# Placeholder macro written by tools/chip_assembly/macros.py
# kind: tile; a die-assembly tile at 1/4 scale less the die channel; operand in and result out registered at its spine-facing edge (the physical tile's edge registers, ot_chip_v41x_ptile NP stages); routes M2-M7 inside (obstructed), die wiring passes over it on M8/M9
VERSION 5.7 ;
BUSBITCHARS "[]" ;
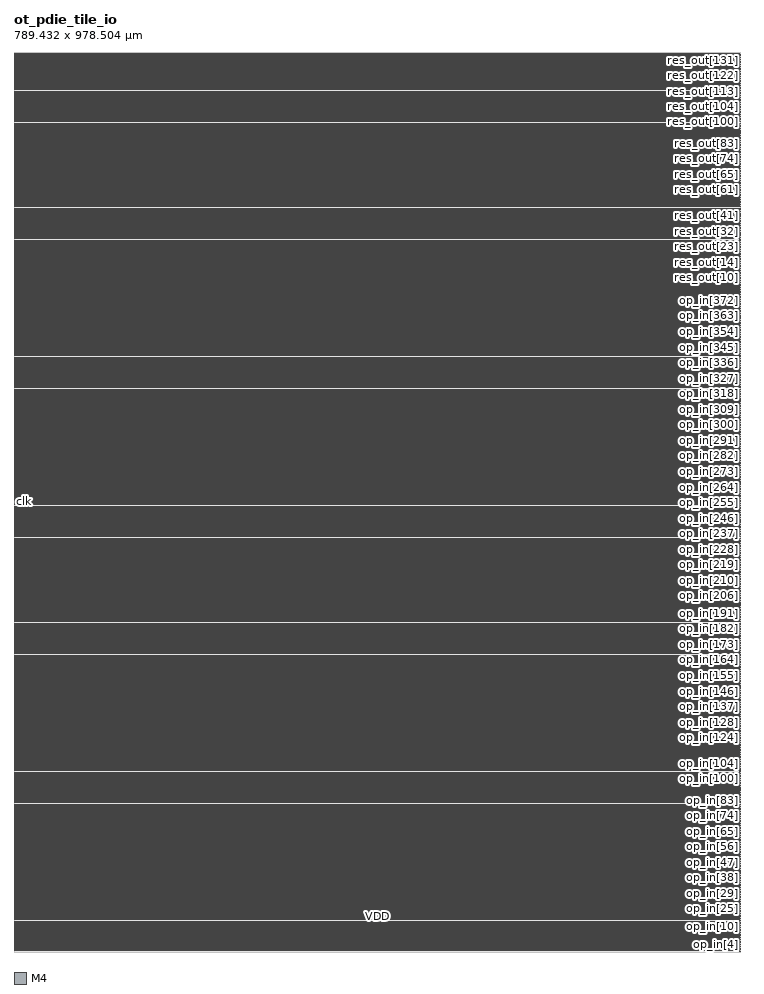
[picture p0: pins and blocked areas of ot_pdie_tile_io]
MACRO ot_pdie_tile_io
  FOREIGN ot_pdie_tile_io 0 0 ;
  SYMMETRY X Y ;
  SIZE 789.432 BY 978.504 ;
  CLASS BLOCK ;
  PIN clk
    DIRECTION INPUT ;
    USE SIGNAL ;
    SHAPE ABUTMENT ;
    PORT
      LAYER M4 ;
      RECT 0.000 489.264 0.192 489.288 ;
    END
  END clk
  PIN op_in[0]
    DIRECTION INPUT ;
    USE SIGNAL ;
    SHAPE ABUTMENT ;
    PORT
      LAYER M4 ;
      RECT 789.240 0.528 789.432 0.552 ;
    END
  END op_in[0]
  PIN op_in[1]
    DIRECTION INPUT ;
    USE SIGNAL ;
    SHAPE ABUTMENT ;
    PORT
      LAYER M4 ;
      RECT 789.240 2.400 789.432 2.424 ;
    END
  END op_in[1]
  PIN op_in[2]
    DIRECTION INPUT ;
    USE SIGNAL ;
    SHAPE ABUTMENT ;
    PORT
      LAYER M4 ;
      RECT 789.240 4.272 789.432 4.296 ;
    END
  END op_in[2]
  PIN op_in[3]
    DIRECTION INPUT ;
    USE SIGNAL ;
    SHAPE ABUTMENT ;
    PORT
      LAYER M4 ;
      RECT 789.240 6.144 789.432 6.168 ;
    END
  END op_in[3]
  PIN op_in[4]
    DIRECTION INPUT ;
    USE SIGNAL ;
    SHAPE ABUTMENT ;
    PORT
      LAYER M4 ;
      RECT 789.240 8.016 789.432 8.040 ;
    END
  END op_in[4]
  PIN op_in[5]
    DIRECTION INPUT ;
    USE SIGNAL ;
    SHAPE ABUTMENT ;
    PORT
      LAYER M4 ;
      RECT 789.240 9.888 789.432 9.912 ;
    END
  END op_in[5]
  PIN op_in[6]
    DIRECTION INPUT ;
    USE SIGNAL ;
    SHAPE ABUTMENT ;
    PORT
      LAYER M4 ;
      RECT 789.240 11.760 789.432 11.784 ;
    END
  END op_in[6]
  PIN op_in[7]
    DIRECTION INPUT ;
    USE SIGNAL ;
    SHAPE ABUTMENT ;
    PORT
      LAYER M4 ;
      RECT 789.240 13.680 789.432 13.704 ;
    END
  END op_in[7]
  PIN op_in[8]
    DIRECTION INPUT ;
    USE SIGNAL ;
    SHAPE ABUTMENT ;
    PORT
      LAYER M4 ;
      RECT 789.240 15.552 789.432 15.576 ;
    END
  END op_in[8]
  PIN op_in[9]
    DIRECTION INPUT ;
    USE SIGNAL ;
    SHAPE ABUTMENT ;
    PORT
      LAYER M4 ;
      RECT 789.240 17.424 789.432 17.448 ;
    END
  END op_in[9]
  PIN op_in[10]
    DIRECTION INPUT ;
    USE SIGNAL ;
    SHAPE ABUTMENT ;
    PORT
      LAYER M4 ;
      RECT 789.240 19.296 789.432 19.320 ;
    END
  END op_in[10]
  PIN op_in[11]
    DIRECTION INPUT ;
    USE SIGNAL ;
    SHAPE ABUTMENT ;
    PORT
      LAYER M4 ;
      RECT 789.240 21.168 789.432 21.192 ;
    END
  END op_in[11]
  PIN op_in[12]
    DIRECTION INPUT ;
    USE SIGNAL ;
    SHAPE ABUTMENT ;
    PORT
      LAYER M4 ;
      RECT 789.240 23.040 789.432 23.064 ;
    END
  END op_in[12]
  PIN op_in[13]
    DIRECTION INPUT ;
    USE SIGNAL ;
    SHAPE ABUTMENT ;
    PORT
      LAYER M4 ;
      RECT 789.240 24.960 789.432 24.984 ;
    END
  END op_in[13]
  PIN op_in[14]
    DIRECTION INPUT ;
    USE SIGNAL ;
    SHAPE ABUTMENT ;
    PORT
      LAYER M4 ;
      RECT 789.240 26.832 789.432 26.856 ;
    END
  END op_in[14]
  PIN op_in[15]
    DIRECTION INPUT ;
    USE SIGNAL ;
    SHAPE ABUTMENT ;
    PORT
      LAYER M4 ;
      RECT 789.240 28.704 789.432 28.728 ;
    END
  END op_in[15]
  PIN op_in[16]
    DIRECTION INPUT ;
    USE SIGNAL ;
    SHAPE ABUTMENT ;
    PORT
      LAYER M4 ;
      RECT 789.240 30.576 789.432 30.600 ;
    END
  END op_in[16]
  PIN op_in[17]
    DIRECTION INPUT ;
    USE SIGNAL ;
    SHAPE ABUTMENT ;
    PORT
      LAYER M4 ;
      RECT 789.240 32.448 789.432 32.472 ;
    END
  END op_in[17]
  PIN op_in[18]
    DIRECTION INPUT ;
    USE SIGNAL ;
    SHAPE ABUTMENT ;
    PORT
      LAYER M4 ;
      RECT 789.240 34.320 789.432 34.344 ;
    END
  END op_in[18]
  PIN op_in[19]
    DIRECTION INPUT ;
    USE SIGNAL ;
    SHAPE ABUTMENT ;
    PORT
      LAYER M4 ;
      RECT 789.240 36.240 789.432 36.264 ;
    END
  END op_in[19]
  PIN op_in[20]
    DIRECTION INPUT ;
    USE SIGNAL ;
    SHAPE ABUTMENT ;
    PORT
      LAYER M4 ;
      RECT 789.240 38.112 789.432 38.136 ;
    END
  END op_in[20]
  PIN op_in[21]
    DIRECTION INPUT ;
    USE SIGNAL ;
    SHAPE ABUTMENT ;
    PORT
      LAYER M4 ;
      RECT 789.240 39.984 789.432 40.008 ;
    END
  END op_in[21]
  PIN op_in[22]
    DIRECTION INPUT ;
    USE SIGNAL ;
    SHAPE ABUTMENT ;
    PORT
      LAYER M4 ;
      RECT 789.240 41.856 789.432 41.880 ;
    END
  END op_in[22]
  PIN op_in[23]
    DIRECTION INPUT ;
    USE SIGNAL ;
    SHAPE ABUTMENT ;
    PORT
      LAYER M4 ;
      RECT 789.240 43.728 789.432 43.752 ;
    END
  END op_in[23]
  PIN op_in[24]
    DIRECTION INPUT ;
    USE SIGNAL ;
    SHAPE ABUTMENT ;
    PORT
      LAYER M4 ;
      RECT 789.240 45.600 789.432 45.624 ;
    END
  END op_in[24]
  PIN op_in[25]
    DIRECTION INPUT ;
    USE SIGNAL ;
    SHAPE ABUTMENT ;
    PORT
      LAYER M4 ;
      RECT 789.240 47.520 789.432 47.544 ;
    END
  END op_in[25]
  PIN op_in[26]
    DIRECTION INPUT ;
    USE SIGNAL ;
    SHAPE ABUTMENT ;
    PORT
      LAYER M4 ;
      RECT 789.240 49.392 789.432 49.416 ;
    END
  END op_in[26]
  PIN op_in[27]
    DIRECTION INPUT ;
    USE SIGNAL ;
    SHAPE ABUTMENT ;
    PORT
      LAYER M4 ;
      RECT 789.240 51.264 789.432 51.288 ;
    END
  END op_in[27]
  PIN op_in[28]
    DIRECTION INPUT ;
    USE SIGNAL ;
    SHAPE ABUTMENT ;
    PORT
      LAYER M4 ;
      RECT 789.240 53.136 789.432 53.160 ;
    END
  END op_in[28]
  PIN op_in[29]
    DIRECTION INPUT ;
    USE SIGNAL ;
    SHAPE ABUTMENT ;
    PORT
      LAYER M4 ;
      RECT 789.240 55.008 789.432 55.032 ;
    END
  END op_in[29]
  PIN op_in[30]
    DIRECTION INPUT ;
    USE SIGNAL ;
    SHAPE ABUTMENT ;
    PORT
      LAYER M4 ;
      RECT 789.240 56.880 789.432 56.904 ;
    END
  END op_in[30]
  PIN op_in[31]
    DIRECTION INPUT ;
    USE SIGNAL ;
    SHAPE ABUTMENT ;
    PORT
      LAYER M4 ;
      RECT 789.240 58.800 789.432 58.824 ;
    END
  END op_in[31]
  PIN op_in[32]
    DIRECTION INPUT ;
    USE SIGNAL ;
    SHAPE ABUTMENT ;
    PORT
      LAYER M4 ;
      RECT 789.240 60.672 789.432 60.696 ;
    END
  END op_in[32]
  PIN op_in[33]
    DIRECTION INPUT ;
    USE SIGNAL ;
    SHAPE ABUTMENT ;
    PORT
      LAYER M4 ;
      RECT 789.240 62.544 789.432 62.568 ;
    END
  END op_in[33]
  PIN op_in[34]
    DIRECTION INPUT ;
    USE SIGNAL ;
    SHAPE ABUTMENT ;
    PORT
      LAYER M4 ;
      RECT 789.240 64.416 789.432 64.440 ;
    END
  END op_in[34]
  PIN op_in[35]
    DIRECTION INPUT ;
    USE SIGNAL ;
    SHAPE ABUTMENT ;
    PORT
      LAYER M4 ;
      RECT 789.240 66.288 789.432 66.312 ;
    END
  END op_in[35]
  PIN op_in[36]
    DIRECTION INPUT ;
    USE SIGNAL ;
    SHAPE ABUTMENT ;
    PORT
      LAYER M4 ;
      RECT 789.240 68.160 789.432 68.184 ;
    END
  END op_in[36]
  PIN op_in[37]
    DIRECTION INPUT ;
    USE SIGNAL ;
    SHAPE ABUTMENT ;
    PORT
      LAYER M4 ;
      RECT 789.240 70.032 789.432 70.056 ;
    END
  END op_in[37]
  PIN op_in[38]
    DIRECTION INPUT ;
    USE SIGNAL ;
    SHAPE ABUTMENT ;
    PORT
      LAYER M4 ;
      RECT 789.240 71.952 789.432 71.976 ;
    END
  END op_in[38]
  PIN op_in[39]
    DIRECTION INPUT ;
    USE SIGNAL ;
    SHAPE ABUTMENT ;
    PORT
      LAYER M4 ;
      RECT 789.240 73.824 789.432 73.848 ;
    END
  END op_in[39]
  PIN op_in[40]
    DIRECTION INPUT ;
    USE SIGNAL ;
    SHAPE ABUTMENT ;
    PORT
      LAYER M4 ;
      RECT 789.240 75.696 789.432 75.720 ;
    END
  END op_in[40]
  PIN op_in[41]
    DIRECTION INPUT ;
    USE SIGNAL ;
    SHAPE ABUTMENT ;
    PORT
      LAYER M4 ;
      RECT 789.240 77.568 789.432 77.592 ;
    END
  END op_in[41]
  PIN op_in[42]
    DIRECTION INPUT ;
    USE SIGNAL ;
    SHAPE ABUTMENT ;
    PORT
      LAYER M4 ;
      RECT 789.240 79.440 789.432 79.464 ;
    END
  END op_in[42]
  PIN op_in[43]
    DIRECTION INPUT ;
    USE SIGNAL ;
    SHAPE ABUTMENT ;
    PORT
      LAYER M4 ;
      RECT 789.240 81.312 789.432 81.336 ;
    END
  END op_in[43]
  PIN op_in[44]
    DIRECTION INPUT ;
    USE SIGNAL ;
    SHAPE ABUTMENT ;
    PORT
      LAYER M4 ;
      RECT 789.240 83.232 789.432 83.256 ;
    END
  END op_in[44]
  PIN op_in[45]
    DIRECTION INPUT ;
    USE SIGNAL ;
    SHAPE ABUTMENT ;
    PORT
      LAYER M4 ;
      RECT 789.240 85.104 789.432 85.128 ;
    END
  END op_in[45]
  PIN op_in[46]
    DIRECTION INPUT ;
    USE SIGNAL ;
    SHAPE ABUTMENT ;
    PORT
      LAYER M4 ;
      RECT 789.240 86.976 789.432 87.000 ;
    END
  END op_in[46]
  PIN op_in[47]
    DIRECTION INPUT ;
    USE SIGNAL ;
    SHAPE ABUTMENT ;
    PORT
      LAYER M4 ;
      RECT 789.240 88.848 789.432 88.872 ;
    END
  END op_in[47]
  PIN op_in[48]
    DIRECTION INPUT ;
    USE SIGNAL ;
    SHAPE ABUTMENT ;
    PORT
      LAYER M4 ;
      RECT 789.240 90.720 789.432 90.744 ;
    END
  END op_in[48]
  PIN op_in[49]
    DIRECTION INPUT ;
    USE SIGNAL ;
    SHAPE ABUTMENT ;
    PORT
      LAYER M4 ;
      RECT 789.240 92.592 789.432 92.616 ;
    END
  END op_in[49]
  PIN op_in[50]
    DIRECTION INPUT ;
    USE SIGNAL ;
    SHAPE ABUTMENT ;
    PORT
      LAYER M4 ;
      RECT 789.240 94.512 789.432 94.536 ;
    END
  END op_in[50]
  PIN op_in[51]
    DIRECTION INPUT ;
    USE SIGNAL ;
    SHAPE ABUTMENT ;
    PORT
      LAYER M4 ;
      RECT 789.240 96.384 789.432 96.408 ;
    END
  END op_in[51]
  PIN op_in[52]
    DIRECTION INPUT ;
    USE SIGNAL ;
    SHAPE ABUTMENT ;
    PORT
      LAYER M4 ;
      RECT 789.240 98.256 789.432 98.280 ;
    END
  END op_in[52]
  PIN op_in[53]
    DIRECTION INPUT ;
    USE SIGNAL ;
    SHAPE ABUTMENT ;
    PORT
      LAYER M4 ;
      RECT 789.240 100.128 789.432 100.152 ;
    END
  END op_in[53]
  PIN op_in[54]
    DIRECTION INPUT ;
    USE SIGNAL ;
    SHAPE ABUTMENT ;
    PORT
      LAYER M4 ;
      RECT 789.240 102.000 789.432 102.024 ;
    END
  END op_in[54]
  PIN op_in[55]
    DIRECTION INPUT ;
    USE SIGNAL ;
    SHAPE ABUTMENT ;
    PORT
      LAYER M4 ;
      RECT 789.240 103.872 789.432 103.896 ;
    END
  END op_in[55]
  PIN op_in[56]
    DIRECTION INPUT ;
    USE SIGNAL ;
    SHAPE ABUTMENT ;
    PORT
      LAYER M4 ;
      RECT 789.240 105.792 789.432 105.816 ;
    END
  END op_in[56]
  PIN op_in[57]
    DIRECTION INPUT ;
    USE SIGNAL ;
    SHAPE ABUTMENT ;
    PORT
      LAYER M4 ;
      RECT 789.240 107.664 789.432 107.688 ;
    END
  END op_in[57]
  PIN op_in[58]
    DIRECTION INPUT ;
    USE SIGNAL ;
    SHAPE ABUTMENT ;
    PORT
      LAYER M4 ;
      RECT 789.240 109.536 789.432 109.560 ;
    END
  END op_in[58]
  PIN op_in[59]
    DIRECTION INPUT ;
    USE SIGNAL ;
    SHAPE ABUTMENT ;
    PORT
      LAYER M4 ;
      RECT 789.240 111.408 789.432 111.432 ;
    END
  END op_in[59]
  PIN op_in[60]
    DIRECTION INPUT ;
    USE SIGNAL ;
    SHAPE ABUTMENT ;
    PORT
      LAYER M4 ;
      RECT 789.240 113.280 789.432 113.304 ;
    END
  END op_in[60]
  PIN op_in[61]
    DIRECTION INPUT ;
    USE SIGNAL ;
    SHAPE ABUTMENT ;
    PORT
      LAYER M4 ;
      RECT 789.240 115.152 789.432 115.176 ;
    END
  END op_in[61]
  PIN op_in[62]
    DIRECTION INPUT ;
    USE SIGNAL ;
    SHAPE ABUTMENT ;
    PORT
      LAYER M4 ;
      RECT 789.240 117.072 789.432 117.096 ;
    END
  END op_in[62]
  PIN op_in[63]
    DIRECTION INPUT ;
    USE SIGNAL ;
    SHAPE ABUTMENT ;
    PORT
      LAYER M4 ;
      RECT 789.240 118.944 789.432 118.968 ;
    END
  END op_in[63]
  PIN op_in[64]
    DIRECTION INPUT ;
    USE SIGNAL ;
    SHAPE ABUTMENT ;
    PORT
      LAYER M4 ;
      RECT 789.240 120.816 789.432 120.840 ;
    END
  END op_in[64]
  PIN op_in[65]
    DIRECTION INPUT ;
    USE SIGNAL ;
    SHAPE ABUTMENT ;
    PORT
      LAYER M4 ;
      RECT 789.240 122.688 789.432 122.712 ;
    END
  END op_in[65]
  PIN op_in[66]
    DIRECTION INPUT ;
    USE SIGNAL ;
    SHAPE ABUTMENT ;
    PORT
      LAYER M4 ;
      RECT 789.240 124.560 789.432 124.584 ;
    END
  END op_in[66]
  PIN op_in[67]
    DIRECTION INPUT ;
    USE SIGNAL ;
    SHAPE ABUTMENT ;
    PORT
      LAYER M4 ;
      RECT 789.240 126.432 789.432 126.456 ;
    END
  END op_in[67]
  PIN op_in[68]
    DIRECTION INPUT ;
    USE SIGNAL ;
    SHAPE ABUTMENT ;
    PORT
      LAYER M4 ;
      RECT 789.240 128.304 789.432 128.328 ;
    END
  END op_in[68]
  PIN op_in[69]
    DIRECTION INPUT ;
    USE SIGNAL ;
    SHAPE ABUTMENT ;
    PORT
      LAYER M4 ;
      RECT 789.240 130.224 789.432 130.248 ;
    END
  END op_in[69]
  PIN op_in[70]
    DIRECTION INPUT ;
    USE SIGNAL ;
    SHAPE ABUTMENT ;
    PORT
      LAYER M4 ;
      RECT 789.240 132.096 789.432 132.120 ;
    END
  END op_in[70]
  PIN op_in[71]
    DIRECTION INPUT ;
    USE SIGNAL ;
    SHAPE ABUTMENT ;
    PORT
      LAYER M4 ;
      RECT 789.240 133.968 789.432 133.992 ;
    END
  END op_in[71]
  PIN op_in[72]
    DIRECTION INPUT ;
    USE SIGNAL ;
    SHAPE ABUTMENT ;
    PORT
      LAYER M4 ;
      RECT 789.240 135.840 789.432 135.864 ;
    END
  END op_in[72]
  PIN op_in[73]
    DIRECTION INPUT ;
    USE SIGNAL ;
    SHAPE ABUTMENT ;
    PORT
      LAYER M4 ;
      RECT 789.240 137.712 789.432 137.736 ;
    END
  END op_in[73]
  PIN op_in[74]
    DIRECTION INPUT ;
    USE SIGNAL ;
    SHAPE ABUTMENT ;
    PORT
      LAYER M4 ;
      RECT 789.240 139.584 789.432 139.608 ;
    END
  END op_in[74]
  PIN op_in[75]
    DIRECTION INPUT ;
    USE SIGNAL ;
    SHAPE ABUTMENT ;
    PORT
      LAYER M4 ;
      RECT 789.240 141.504 789.432 141.528 ;
    END
  END op_in[75]
  PIN op_in[76]
    DIRECTION INPUT ;
    USE SIGNAL ;
    SHAPE ABUTMENT ;
    PORT
      LAYER M4 ;
      RECT 789.240 143.376 789.432 143.400 ;
    END
  END op_in[76]
  PIN op_in[77]
    DIRECTION INPUT ;
    USE SIGNAL ;
    SHAPE ABUTMENT ;
    PORT
      LAYER M4 ;
      RECT 789.240 145.248 789.432 145.272 ;
    END
  END op_in[77]
  PIN op_in[78]
    DIRECTION INPUT ;
    USE SIGNAL ;
    SHAPE ABUTMENT ;
    PORT
      LAYER M4 ;
      RECT 789.240 147.120 789.432 147.144 ;
    END
  END op_in[78]
  PIN op_in[79]
    DIRECTION INPUT ;
    USE SIGNAL ;
    SHAPE ABUTMENT ;
    PORT
      LAYER M4 ;
      RECT 789.240 148.992 789.432 149.016 ;
    END
  END op_in[79]
  PIN op_in[80]
    DIRECTION INPUT ;
    USE SIGNAL ;
    SHAPE ABUTMENT ;
    PORT
      LAYER M4 ;
      RECT 789.240 150.864 789.432 150.888 ;
    END
  END op_in[80]
  PIN op_in[81]
    DIRECTION INPUT ;
    USE SIGNAL ;
    SHAPE ABUTMENT ;
    PORT
      LAYER M4 ;
      RECT 789.240 152.784 789.432 152.808 ;
    END
  END op_in[81]
  PIN op_in[82]
    DIRECTION INPUT ;
    USE SIGNAL ;
    SHAPE ABUTMENT ;
    PORT
      LAYER M4 ;
      RECT 789.240 154.656 789.432 154.680 ;
    END
  END op_in[82]
  PIN op_in[83]
    DIRECTION INPUT ;
    USE SIGNAL ;
    SHAPE ABUTMENT ;
    PORT
      LAYER M4 ;
      RECT 789.240 156.528 789.432 156.552 ;
    END
  END op_in[83]
  PIN op_in[84]
    DIRECTION INPUT ;
    USE SIGNAL ;
    SHAPE ABUTMENT ;
    PORT
      LAYER M4 ;
      RECT 789.240 158.400 789.432 158.424 ;
    END
  END op_in[84]
  PIN op_in[85]
    DIRECTION INPUT ;
    USE SIGNAL ;
    SHAPE ABUTMENT ;
    PORT
      LAYER M4 ;
      RECT 789.240 160.272 789.432 160.296 ;
    END
  END op_in[85]
  PIN op_in[86]
    DIRECTION INPUT ;
    USE SIGNAL ;
    SHAPE ABUTMENT ;
    PORT
      LAYER M4 ;
      RECT 789.240 162.144 789.432 162.168 ;
    END
  END op_in[86]
  PIN op_in[87]
    DIRECTION INPUT ;
    USE SIGNAL ;
    SHAPE ABUTMENT ;
    PORT
      LAYER M4 ;
      RECT 789.240 164.064 789.432 164.088 ;
    END
  END op_in[87]
  PIN op_in[88]
    DIRECTION INPUT ;
    USE SIGNAL ;
    SHAPE ABUTMENT ;
    PORT
      LAYER M4 ;
      RECT 789.240 165.936 789.432 165.960 ;
    END
  END op_in[88]
  PIN op_in[89]
    DIRECTION INPUT ;
    USE SIGNAL ;
    SHAPE ABUTMENT ;
    PORT
      LAYER M4 ;
      RECT 789.240 167.808 789.432 167.832 ;
    END
  END op_in[89]
  PIN op_in[90]
    DIRECTION INPUT ;
    USE SIGNAL ;
    SHAPE ABUTMENT ;
    PORT
      LAYER M4 ;
      RECT 789.240 169.680 789.432 169.704 ;
    END
  END op_in[90]
  PIN op_in[91]
    DIRECTION INPUT ;
    USE SIGNAL ;
    SHAPE ABUTMENT ;
    PORT
      LAYER M4 ;
      RECT 789.240 171.552 789.432 171.576 ;
    END
  END op_in[91]
  PIN op_in[92]
    DIRECTION INPUT ;
    USE SIGNAL ;
    SHAPE ABUTMENT ;
    PORT
      LAYER M4 ;
      RECT 789.240 173.424 789.432 173.448 ;
    END
  END op_in[92]
  PIN op_in[93]
    DIRECTION INPUT ;
    USE SIGNAL ;
    SHAPE ABUTMENT ;
    PORT
      LAYER M4 ;
      RECT 789.240 175.344 789.432 175.368 ;
    END
  END op_in[93]
  PIN op_in[94]
    DIRECTION INPUT ;
    USE SIGNAL ;
    SHAPE ABUTMENT ;
    PORT
      LAYER M4 ;
      RECT 789.240 177.216 789.432 177.240 ;
    END
  END op_in[94]
  PIN op_in[95]
    DIRECTION INPUT ;
    USE SIGNAL ;
    SHAPE ABUTMENT ;
    PORT
      LAYER M4 ;
      RECT 789.240 179.088 789.432 179.112 ;
    END
  END op_in[95]
  PIN op_in[96]
    DIRECTION INPUT ;
    USE SIGNAL ;
    SHAPE ABUTMENT ;
    PORT
      LAYER M4 ;
      RECT 789.240 180.960 789.432 180.984 ;
    END
  END op_in[96]
  PIN op_in[97]
    DIRECTION INPUT ;
    USE SIGNAL ;
    SHAPE ABUTMENT ;
    PORT
      LAYER M4 ;
      RECT 789.240 182.832 789.432 182.856 ;
    END
  END op_in[97]
  PIN op_in[98]
    DIRECTION INPUT ;
    USE SIGNAL ;
    SHAPE ABUTMENT ;
    PORT
      LAYER M4 ;
      RECT 789.240 184.704 789.432 184.728 ;
    END
  END op_in[98]
  PIN op_in[99]
    DIRECTION INPUT ;
    USE SIGNAL ;
    SHAPE ABUTMENT ;
    PORT
      LAYER M4 ;
      RECT 789.240 186.576 789.432 186.600 ;
    END
  END op_in[99]
  PIN op_in[100]
    DIRECTION INPUT ;
    USE SIGNAL ;
    SHAPE ABUTMENT ;
    PORT
      LAYER M4 ;
      RECT 789.240 188.496 789.432 188.520 ;
    END
  END op_in[100]
  PIN op_in[101]
    DIRECTION INPUT ;
    USE SIGNAL ;
    SHAPE ABUTMENT ;
    PORT
      LAYER M4 ;
      RECT 789.240 190.368 789.432 190.392 ;
    END
  END op_in[101]
  PIN op_in[102]
    DIRECTION INPUT ;
    USE SIGNAL ;
    SHAPE ABUTMENT ;
    PORT
      LAYER M4 ;
      RECT 789.240 192.240 789.432 192.264 ;
    END
  END op_in[102]
  PIN op_in[103]
    DIRECTION INPUT ;
    USE SIGNAL ;
    SHAPE ABUTMENT ;
    PORT
      LAYER M4 ;
      RECT 789.240 194.112 789.432 194.136 ;
    END
  END op_in[103]
  PIN op_in[104]
    DIRECTION INPUT ;
    USE SIGNAL ;
    SHAPE ABUTMENT ;
    PORT
      LAYER M4 ;
      RECT 789.240 195.984 789.432 196.008 ;
    END
  END op_in[104]
  PIN op_in[105]
    DIRECTION INPUT ;
    USE SIGNAL ;
    SHAPE ABUTMENT ;
    PORT
      LAYER M4 ;
      RECT 789.240 197.856 789.432 197.880 ;
    END
  END op_in[105]
  PIN op_in[106]
    DIRECTION INPUT ;
    USE SIGNAL ;
    SHAPE ABUTMENT ;
    PORT
      LAYER M4 ;
      RECT 789.240 199.776 789.432 199.800 ;
    END
  END op_in[106]
  PIN op_in[107]
    DIRECTION INPUT ;
    USE SIGNAL ;
    SHAPE ABUTMENT ;
    PORT
      LAYER M4 ;
      RECT 789.240 201.648 789.432 201.672 ;
    END
  END op_in[107]
  PIN op_in[108]
    DIRECTION INPUT ;
    USE SIGNAL ;
    SHAPE ABUTMENT ;
    PORT
      LAYER M4 ;
      RECT 789.240 203.520 789.432 203.544 ;
    END
  END op_in[108]
  PIN op_in[109]
    DIRECTION INPUT ;
    USE SIGNAL ;
    SHAPE ABUTMENT ;
    PORT
      LAYER M4 ;
      RECT 789.240 205.392 789.432 205.416 ;
    END
  END op_in[109]
  PIN op_in[110]
    DIRECTION INPUT ;
    USE SIGNAL ;
    SHAPE ABUTMENT ;
    PORT
      LAYER M4 ;
      RECT 789.240 207.264 789.432 207.288 ;
    END
  END op_in[110]
  PIN op_in[111]
    DIRECTION INPUT ;
    USE SIGNAL ;
    SHAPE ABUTMENT ;
    PORT
      LAYER M4 ;
      RECT 789.240 209.136 789.432 209.160 ;
    END
  END op_in[111]
  PIN op_in[112]
    DIRECTION INPUT ;
    USE SIGNAL ;
    SHAPE ABUTMENT ;
    PORT
      LAYER M4 ;
      RECT 789.240 211.056 789.432 211.080 ;
    END
  END op_in[112]
  PIN op_in[113]
    DIRECTION INPUT ;
    USE SIGNAL ;
    SHAPE ABUTMENT ;
    PORT
      LAYER M4 ;
      RECT 789.240 212.928 789.432 212.952 ;
    END
  END op_in[113]
  PIN op_in[114]
    DIRECTION INPUT ;
    USE SIGNAL ;
    SHAPE ABUTMENT ;
    PORT
      LAYER M4 ;
      RECT 789.240 214.800 789.432 214.824 ;
    END
  END op_in[114]
  PIN op_in[115]
    DIRECTION INPUT ;
    USE SIGNAL ;
    SHAPE ABUTMENT ;
    PORT
      LAYER M4 ;
      RECT 789.240 216.672 789.432 216.696 ;
    END
  END op_in[115]
  PIN op_in[116]
    DIRECTION INPUT ;
    USE SIGNAL ;
    SHAPE ABUTMENT ;
    PORT
      LAYER M4 ;
      RECT 789.240 218.544 789.432 218.568 ;
    END
  END op_in[116]
  PIN op_in[117]
    DIRECTION INPUT ;
    USE SIGNAL ;
    SHAPE ABUTMENT ;
    PORT
      LAYER M4 ;
      RECT 789.240 220.416 789.432 220.440 ;
    END
  END op_in[117]
  PIN op_in[118]
    DIRECTION INPUT ;
    USE SIGNAL ;
    SHAPE ABUTMENT ;
    PORT
      LAYER M4 ;
      RECT 789.240 222.336 789.432 222.360 ;
    END
  END op_in[118]
  PIN op_in[119]
    DIRECTION INPUT ;
    USE SIGNAL ;
    SHAPE ABUTMENT ;
    PORT
      LAYER M4 ;
      RECT 789.240 224.208 789.432 224.232 ;
    END
  END op_in[119]
  PIN op_in[120]
    DIRECTION INPUT ;
    USE SIGNAL ;
    SHAPE ABUTMENT ;
    PORT
      LAYER M4 ;
      RECT 789.240 226.080 789.432 226.104 ;
    END
  END op_in[120]
  PIN op_in[121]
    DIRECTION INPUT ;
    USE SIGNAL ;
    SHAPE ABUTMENT ;
    PORT
      LAYER M4 ;
      RECT 789.240 227.952 789.432 227.976 ;
    END
  END op_in[121]
  PIN op_in[122]
    DIRECTION INPUT ;
    USE SIGNAL ;
    SHAPE ABUTMENT ;
    PORT
      LAYER M4 ;
      RECT 789.240 229.824 789.432 229.848 ;
    END
  END op_in[122]
  PIN op_in[123]
    DIRECTION INPUT ;
    USE SIGNAL ;
    SHAPE ABUTMENT ;
    PORT
      LAYER M4 ;
      RECT 789.240 231.696 789.432 231.720 ;
    END
  END op_in[123]
  PIN op_in[124]
    DIRECTION INPUT ;
    USE SIGNAL ;
    SHAPE ABUTMENT ;
    PORT
      LAYER M4 ;
      RECT 789.240 233.616 789.432 233.640 ;
    END
  END op_in[124]
  PIN op_in[125]
    DIRECTION INPUT ;
    USE SIGNAL ;
    SHAPE ABUTMENT ;
    PORT
      LAYER M4 ;
      RECT 789.240 235.488 789.432 235.512 ;
    END
  END op_in[125]
  PIN op_in[126]
    DIRECTION INPUT ;
    USE SIGNAL ;
    SHAPE ABUTMENT ;
    PORT
      LAYER M4 ;
      RECT 789.240 237.360 789.432 237.384 ;
    END
  END op_in[126]
  PIN op_in[127]
    DIRECTION INPUT ;
    USE SIGNAL ;
    SHAPE ABUTMENT ;
    PORT
      LAYER M4 ;
      RECT 789.240 239.232 789.432 239.256 ;
    END
  END op_in[127]
  PIN op_in[128]
    DIRECTION INPUT ;
    USE SIGNAL ;
    SHAPE ABUTMENT ;
    PORT
      LAYER M4 ;
      RECT 789.240 241.104 789.432 241.128 ;
    END
  END op_in[128]
  PIN op_in[129]
    DIRECTION INPUT ;
    USE SIGNAL ;
    SHAPE ABUTMENT ;
    PORT
      LAYER M4 ;
      RECT 789.240 242.976 789.432 243.000 ;
    END
  END op_in[129]
  PIN op_in[130]
    DIRECTION INPUT ;
    USE SIGNAL ;
    SHAPE ABUTMENT ;
    PORT
      LAYER M4 ;
      RECT 789.240 244.896 789.432 244.920 ;
    END
  END op_in[130]
  PIN op_in[131]
    DIRECTION INPUT ;
    USE SIGNAL ;
    SHAPE ABUTMENT ;
    PORT
      LAYER M4 ;
      RECT 789.240 246.768 789.432 246.792 ;
    END
  END op_in[131]
  PIN op_in[132]
    DIRECTION INPUT ;
    USE SIGNAL ;
    SHAPE ABUTMENT ;
    PORT
      LAYER M4 ;
      RECT 789.240 248.640 789.432 248.664 ;
    END
  END op_in[132]
  PIN op_in[133]
    DIRECTION INPUT ;
    USE SIGNAL ;
    SHAPE ABUTMENT ;
    PORT
      LAYER M4 ;
      RECT 789.240 250.512 789.432 250.536 ;
    END
  END op_in[133]
  PIN op_in[134]
    DIRECTION INPUT ;
    USE SIGNAL ;
    SHAPE ABUTMENT ;
    PORT
      LAYER M4 ;
      RECT 789.240 252.384 789.432 252.408 ;
    END
  END op_in[134]
  PIN op_in[135]
    DIRECTION INPUT ;
    USE SIGNAL ;
    SHAPE ABUTMENT ;
    PORT
      LAYER M4 ;
      RECT 789.240 254.256 789.432 254.280 ;
    END
  END op_in[135]
  PIN op_in[136]
    DIRECTION INPUT ;
    USE SIGNAL ;
    SHAPE ABUTMENT ;
    PORT
      LAYER M4 ;
      RECT 789.240 256.128 789.432 256.152 ;
    END
  END op_in[136]
  PIN op_in[137]
    DIRECTION INPUT ;
    USE SIGNAL ;
    SHAPE ABUTMENT ;
    PORT
      LAYER M4 ;
      RECT 789.240 258.048 789.432 258.072 ;
    END
  END op_in[137]
  PIN op_in[138]
    DIRECTION INPUT ;
    USE SIGNAL ;
    SHAPE ABUTMENT ;
    PORT
      LAYER M4 ;
      RECT 789.240 259.920 789.432 259.944 ;
    END
  END op_in[138]
  PIN op_in[139]
    DIRECTION INPUT ;
    USE SIGNAL ;
    SHAPE ABUTMENT ;
    PORT
      LAYER M4 ;
      RECT 789.240 261.792 789.432 261.816 ;
    END
  END op_in[139]
  PIN op_in[140]
    DIRECTION INPUT ;
    USE SIGNAL ;
    SHAPE ABUTMENT ;
    PORT
      LAYER M4 ;
      RECT 789.240 263.664 789.432 263.688 ;
    END
  END op_in[140]
  PIN op_in[141]
    DIRECTION INPUT ;
    USE SIGNAL ;
    SHAPE ABUTMENT ;
    PORT
      LAYER M4 ;
      RECT 789.240 265.536 789.432 265.560 ;
    END
  END op_in[141]
  PIN op_in[142]
    DIRECTION INPUT ;
    USE SIGNAL ;
    SHAPE ABUTMENT ;
    PORT
      LAYER M4 ;
      RECT 789.240 267.408 789.432 267.432 ;
    END
  END op_in[142]
  PIN op_in[143]
    DIRECTION INPUT ;
    USE SIGNAL ;
    SHAPE ABUTMENT ;
    PORT
      LAYER M4 ;
      RECT 789.240 269.328 789.432 269.352 ;
    END
  END op_in[143]
  PIN op_in[144]
    DIRECTION INPUT ;
    USE SIGNAL ;
    SHAPE ABUTMENT ;
    PORT
      LAYER M4 ;
      RECT 789.240 271.200 789.432 271.224 ;
    END
  END op_in[144]
  PIN op_in[145]
    DIRECTION INPUT ;
    USE SIGNAL ;
    SHAPE ABUTMENT ;
    PORT
      LAYER M4 ;
      RECT 789.240 273.072 789.432 273.096 ;
    END
  END op_in[145]
  PIN op_in[146]
    DIRECTION INPUT ;
    USE SIGNAL ;
    SHAPE ABUTMENT ;
    PORT
      LAYER M4 ;
      RECT 789.240 274.944 789.432 274.968 ;
    END
  END op_in[146]
  PIN op_in[147]
    DIRECTION INPUT ;
    USE SIGNAL ;
    SHAPE ABUTMENT ;
    PORT
      LAYER M4 ;
      RECT 789.240 276.816 789.432 276.840 ;
    END
  END op_in[147]
  PIN op_in[148]
    DIRECTION INPUT ;
    USE SIGNAL ;
    SHAPE ABUTMENT ;
    PORT
      LAYER M4 ;
      RECT 789.240 278.688 789.432 278.712 ;
    END
  END op_in[148]
  PIN op_in[149]
    DIRECTION INPUT ;
    USE SIGNAL ;
    SHAPE ABUTMENT ;
    PORT
      LAYER M4 ;
      RECT 789.240 280.608 789.432 280.632 ;
    END
  END op_in[149]
  PIN op_in[150]
    DIRECTION INPUT ;
    USE SIGNAL ;
    SHAPE ABUTMENT ;
    PORT
      LAYER M4 ;
      RECT 789.240 282.480 789.432 282.504 ;
    END
  END op_in[150]
  PIN op_in[151]
    DIRECTION INPUT ;
    USE SIGNAL ;
    SHAPE ABUTMENT ;
    PORT
      LAYER M4 ;
      RECT 789.240 284.352 789.432 284.376 ;
    END
  END op_in[151]
  PIN op_in[152]
    DIRECTION INPUT ;
    USE SIGNAL ;
    SHAPE ABUTMENT ;
    PORT
      LAYER M4 ;
      RECT 789.240 286.224 789.432 286.248 ;
    END
  END op_in[152]
  PIN op_in[153]
    DIRECTION INPUT ;
    USE SIGNAL ;
    SHAPE ABUTMENT ;
    PORT
      LAYER M4 ;
      RECT 789.240 288.096 789.432 288.120 ;
    END
  END op_in[153]
  PIN op_in[154]
    DIRECTION INPUT ;
    USE SIGNAL ;
    SHAPE ABUTMENT ;
    PORT
      LAYER M4 ;
      RECT 789.240 289.968 789.432 289.992 ;
    END
  END op_in[154]
  PIN op_in[155]
    DIRECTION INPUT ;
    USE SIGNAL ;
    SHAPE ABUTMENT ;
    PORT
      LAYER M4 ;
      RECT 789.240 291.888 789.432 291.912 ;
    END
  END op_in[155]
  PIN op_in[156]
    DIRECTION INPUT ;
    USE SIGNAL ;
    SHAPE ABUTMENT ;
    PORT
      LAYER M4 ;
      RECT 789.240 293.760 789.432 293.784 ;
    END
  END op_in[156]
  PIN op_in[157]
    DIRECTION INPUT ;
    USE SIGNAL ;
    SHAPE ABUTMENT ;
    PORT
      LAYER M4 ;
      RECT 789.240 295.632 789.432 295.656 ;
    END
  END op_in[157]
  PIN op_in[158]
    DIRECTION INPUT ;
    USE SIGNAL ;
    SHAPE ABUTMENT ;
    PORT
      LAYER M4 ;
      RECT 789.240 297.504 789.432 297.528 ;
    END
  END op_in[158]
  PIN op_in[159]
    DIRECTION INPUT ;
    USE SIGNAL ;
    SHAPE ABUTMENT ;
    PORT
      LAYER M4 ;
      RECT 789.240 299.376 789.432 299.400 ;
    END
  END op_in[159]
  PIN op_in[160]
    DIRECTION INPUT ;
    USE SIGNAL ;
    SHAPE ABUTMENT ;
    PORT
      LAYER M4 ;
      RECT 789.240 301.248 789.432 301.272 ;
    END
  END op_in[160]
  PIN op_in[161]
    DIRECTION INPUT ;
    USE SIGNAL ;
    SHAPE ABUTMENT ;
    PORT
      LAYER M4 ;
      RECT 789.240 303.168 789.432 303.192 ;
    END
  END op_in[161]
  PIN op_in[162]
    DIRECTION INPUT ;
    USE SIGNAL ;
    SHAPE ABUTMENT ;
    PORT
      LAYER M4 ;
      RECT 789.240 305.040 789.432 305.064 ;
    END
  END op_in[162]
  PIN op_in[163]
    DIRECTION INPUT ;
    USE SIGNAL ;
    SHAPE ABUTMENT ;
    PORT
      LAYER M4 ;
      RECT 789.240 306.912 789.432 306.936 ;
    END
  END op_in[163]
  PIN op_in[164]
    DIRECTION INPUT ;
    USE SIGNAL ;
    SHAPE ABUTMENT ;
    PORT
      LAYER M4 ;
      RECT 789.240 308.784 789.432 308.808 ;
    END
  END op_in[164]
  PIN op_in[165]
    DIRECTION INPUT ;
    USE SIGNAL ;
    SHAPE ABUTMENT ;
    PORT
      LAYER M4 ;
      RECT 789.240 310.656 789.432 310.680 ;
    END
  END op_in[165]
  PIN op_in[166]
    DIRECTION INPUT ;
    USE SIGNAL ;
    SHAPE ABUTMENT ;
    PORT
      LAYER M4 ;
      RECT 789.240 312.528 789.432 312.552 ;
    END
  END op_in[166]
  PIN op_in[167]
    DIRECTION INPUT ;
    USE SIGNAL ;
    SHAPE ABUTMENT ;
    PORT
      LAYER M4 ;
      RECT 789.240 314.400 789.432 314.424 ;
    END
  END op_in[167]
  PIN op_in[168]
    DIRECTION INPUT ;
    USE SIGNAL ;
    SHAPE ABUTMENT ;
    PORT
      LAYER M4 ;
      RECT 789.240 316.320 789.432 316.344 ;
    END
  END op_in[168]
  PIN op_in[169]
    DIRECTION INPUT ;
    USE SIGNAL ;
    SHAPE ABUTMENT ;
    PORT
      LAYER M4 ;
      RECT 789.240 318.192 789.432 318.216 ;
    END
  END op_in[169]
  PIN op_in[170]
    DIRECTION INPUT ;
    USE SIGNAL ;
    SHAPE ABUTMENT ;
    PORT
      LAYER M4 ;
      RECT 789.240 320.064 789.432 320.088 ;
    END
  END op_in[170]
  PIN op_in[171]
    DIRECTION INPUT ;
    USE SIGNAL ;
    SHAPE ABUTMENT ;
    PORT
      LAYER M4 ;
      RECT 789.240 321.936 789.432 321.960 ;
    END
  END op_in[171]
  PIN op_in[172]
    DIRECTION INPUT ;
    USE SIGNAL ;
    SHAPE ABUTMENT ;
    PORT
      LAYER M4 ;
      RECT 789.240 323.808 789.432 323.832 ;
    END
  END op_in[172]
  PIN op_in[173]
    DIRECTION INPUT ;
    USE SIGNAL ;
    SHAPE ABUTMENT ;
    PORT
      LAYER M4 ;
      RECT 789.240 325.680 789.432 325.704 ;
    END
  END op_in[173]
  PIN op_in[174]
    DIRECTION INPUT ;
    USE SIGNAL ;
    SHAPE ABUTMENT ;
    PORT
      LAYER M4 ;
      RECT 789.240 327.600 789.432 327.624 ;
    END
  END op_in[174]
  PIN op_in[175]
    DIRECTION INPUT ;
    USE SIGNAL ;
    SHAPE ABUTMENT ;
    PORT
      LAYER M4 ;
      RECT 789.240 329.472 789.432 329.496 ;
    END
  END op_in[175]
  PIN op_in[176]
    DIRECTION INPUT ;
    USE SIGNAL ;
    SHAPE ABUTMENT ;
    PORT
      LAYER M4 ;
      RECT 789.240 331.344 789.432 331.368 ;
    END
  END op_in[176]
  PIN op_in[177]
    DIRECTION INPUT ;
    USE SIGNAL ;
    SHAPE ABUTMENT ;
    PORT
      LAYER M4 ;
      RECT 789.240 333.216 789.432 333.240 ;
    END
  END op_in[177]
  PIN op_in[178]
    DIRECTION INPUT ;
    USE SIGNAL ;
    SHAPE ABUTMENT ;
    PORT
      LAYER M4 ;
      RECT 789.240 335.088 789.432 335.112 ;
    END
  END op_in[178]
  PIN op_in[179]
    DIRECTION INPUT ;
    USE SIGNAL ;
    SHAPE ABUTMENT ;
    PORT
      LAYER M4 ;
      RECT 789.240 336.960 789.432 336.984 ;
    END
  END op_in[179]
  PIN op_in[180]
    DIRECTION INPUT ;
    USE SIGNAL ;
    SHAPE ABUTMENT ;
    PORT
      LAYER M4 ;
      RECT 789.240 338.880 789.432 338.904 ;
    END
  END op_in[180]
  PIN op_in[181]
    DIRECTION INPUT ;
    USE SIGNAL ;
    SHAPE ABUTMENT ;
    PORT
      LAYER M4 ;
      RECT 789.240 340.752 789.432 340.776 ;
    END
  END op_in[181]
  PIN op_in[182]
    DIRECTION INPUT ;
    USE SIGNAL ;
    SHAPE ABUTMENT ;
    PORT
      LAYER M4 ;
      RECT 789.240 342.624 789.432 342.648 ;
    END
  END op_in[182]
  PIN op_in[183]
    DIRECTION INPUT ;
    USE SIGNAL ;
    SHAPE ABUTMENT ;
    PORT
      LAYER M4 ;
      RECT 789.240 344.496 789.432 344.520 ;
    END
  END op_in[183]
  PIN op_in[184]
    DIRECTION INPUT ;
    USE SIGNAL ;
    SHAPE ABUTMENT ;
    PORT
      LAYER M4 ;
      RECT 789.240 346.368 789.432 346.392 ;
    END
  END op_in[184]
  PIN op_in[185]
    DIRECTION INPUT ;
    USE SIGNAL ;
    SHAPE ABUTMENT ;
    PORT
      LAYER M4 ;
      RECT 789.240 348.240 789.432 348.264 ;
    END
  END op_in[185]
  PIN op_in[186]
    DIRECTION INPUT ;
    USE SIGNAL ;
    SHAPE ABUTMENT ;
    PORT
      LAYER M4 ;
      RECT 789.240 350.160 789.432 350.184 ;
    END
  END op_in[186]
  PIN op_in[187]
    DIRECTION INPUT ;
    USE SIGNAL ;
    SHAPE ABUTMENT ;
    PORT
      LAYER M4 ;
      RECT 789.240 352.032 789.432 352.056 ;
    END
  END op_in[187]
  PIN op_in[188]
    DIRECTION INPUT ;
    USE SIGNAL ;
    SHAPE ABUTMENT ;
    PORT
      LAYER M4 ;
      RECT 789.240 353.904 789.432 353.928 ;
    END
  END op_in[188]
  PIN op_in[189]
    DIRECTION INPUT ;
    USE SIGNAL ;
    SHAPE ABUTMENT ;
    PORT
      LAYER M4 ;
      RECT 789.240 355.776 789.432 355.800 ;
    END
  END op_in[189]
  PIN op_in[190]
    DIRECTION INPUT ;
    USE SIGNAL ;
    SHAPE ABUTMENT ;
    PORT
      LAYER M4 ;
      RECT 789.240 357.648 789.432 357.672 ;
    END
  END op_in[190]
  PIN op_in[191]
    DIRECTION INPUT ;
    USE SIGNAL ;
    SHAPE ABUTMENT ;
    PORT
      LAYER M4 ;
      RECT 789.240 359.520 789.432 359.544 ;
    END
  END op_in[191]
  PIN op_in[192]
    DIRECTION INPUT ;
    USE SIGNAL ;
    SHAPE ABUTMENT ;
    PORT
      LAYER M4 ;
      RECT 789.240 361.440 789.432 361.464 ;
    END
  END op_in[192]
  PIN op_in[193]
    DIRECTION INPUT ;
    USE SIGNAL ;
    SHAPE ABUTMENT ;
    PORT
      LAYER M4 ;
      RECT 789.240 363.312 789.432 363.336 ;
    END
  END op_in[193]
  PIN op_in[194]
    DIRECTION INPUT ;
    USE SIGNAL ;
    SHAPE ABUTMENT ;
    PORT
      LAYER M4 ;
      RECT 789.240 365.184 789.432 365.208 ;
    END
  END op_in[194]
  PIN op_in[195]
    DIRECTION INPUT ;
    USE SIGNAL ;
    SHAPE ABUTMENT ;
    PORT
      LAYER M4 ;
      RECT 789.240 367.056 789.432 367.080 ;
    END
  END op_in[195]
  PIN op_in[196]
    DIRECTION INPUT ;
    USE SIGNAL ;
    SHAPE ABUTMENT ;
    PORT
      LAYER M4 ;
      RECT 789.240 368.928 789.432 368.952 ;
    END
  END op_in[196]
  PIN op_in[197]
    DIRECTION INPUT ;
    USE SIGNAL ;
    SHAPE ABUTMENT ;
    PORT
      LAYER M4 ;
      RECT 789.240 370.800 789.432 370.824 ;
    END
  END op_in[197]
  PIN op_in[198]
    DIRECTION INPUT ;
    USE SIGNAL ;
    SHAPE ABUTMENT ;
    PORT
      LAYER M4 ;
      RECT 789.240 372.672 789.432 372.696 ;
    END
  END op_in[198]
  PIN op_in[199]
    DIRECTION INPUT ;
    USE SIGNAL ;
    SHAPE ABUTMENT ;
    PORT
      LAYER M4 ;
      RECT 789.240 374.592 789.432 374.616 ;
    END
  END op_in[199]
  PIN op_in[200]
    DIRECTION INPUT ;
    USE SIGNAL ;
    SHAPE ABUTMENT ;
    PORT
      LAYER M4 ;
      RECT 789.240 376.464 789.432 376.488 ;
    END
  END op_in[200]
  PIN op_in[201]
    DIRECTION INPUT ;
    USE SIGNAL ;
    SHAPE ABUTMENT ;
    PORT
      LAYER M4 ;
      RECT 789.240 378.336 789.432 378.360 ;
    END
  END op_in[201]
  PIN op_in[202]
    DIRECTION INPUT ;
    USE SIGNAL ;
    SHAPE ABUTMENT ;
    PORT
      LAYER M4 ;
      RECT 789.240 380.208 789.432 380.232 ;
    END
  END op_in[202]
  PIN op_in[203]
    DIRECTION INPUT ;
    USE SIGNAL ;
    SHAPE ABUTMENT ;
    PORT
      LAYER M4 ;
      RECT 789.240 382.080 789.432 382.104 ;
    END
  END op_in[203]
  PIN op_in[204]
    DIRECTION INPUT ;
    USE SIGNAL ;
    SHAPE ABUTMENT ;
    PORT
      LAYER M4 ;
      RECT 789.240 383.952 789.432 383.976 ;
    END
  END op_in[204]
  PIN op_in[205]
    DIRECTION INPUT ;
    USE SIGNAL ;
    SHAPE ABUTMENT ;
    PORT
      LAYER M4 ;
      RECT 789.240 385.872 789.432 385.896 ;
    END
  END op_in[205]
  PIN op_in[206]
    DIRECTION INPUT ;
    USE SIGNAL ;
    SHAPE ABUTMENT ;
    PORT
      LAYER M4 ;
      RECT 789.240 387.744 789.432 387.768 ;
    END
  END op_in[206]
  PIN op_in[207]
    DIRECTION INPUT ;
    USE SIGNAL ;
    SHAPE ABUTMENT ;
    PORT
      LAYER M4 ;
      RECT 789.240 389.616 789.432 389.640 ;
    END
  END op_in[207]
  PIN op_in[208]
    DIRECTION INPUT ;
    USE SIGNAL ;
    SHAPE ABUTMENT ;
    PORT
      LAYER M4 ;
      RECT 789.240 391.488 789.432 391.512 ;
    END
  END op_in[208]
  PIN op_in[209]
    DIRECTION INPUT ;
    USE SIGNAL ;
    SHAPE ABUTMENT ;
    PORT
      LAYER M4 ;
      RECT 789.240 393.360 789.432 393.384 ;
    END
  END op_in[209]
  PIN op_in[210]
    DIRECTION INPUT ;
    USE SIGNAL ;
    SHAPE ABUTMENT ;
    PORT
      LAYER M4 ;
      RECT 789.240 395.232 789.432 395.256 ;
    END
  END op_in[210]
  PIN op_in[211]
    DIRECTION INPUT ;
    USE SIGNAL ;
    SHAPE ABUTMENT ;
    PORT
      LAYER M4 ;
      RECT 789.240 397.152 789.432 397.176 ;
    END
  END op_in[211]
  PIN op_in[212]
    DIRECTION INPUT ;
    USE SIGNAL ;
    SHAPE ABUTMENT ;
    PORT
      LAYER M4 ;
      RECT 789.240 399.024 789.432 399.048 ;
    END
  END op_in[212]
  PIN op_in[213]
    DIRECTION INPUT ;
    USE SIGNAL ;
    SHAPE ABUTMENT ;
    PORT
      LAYER M4 ;
      RECT 789.240 400.896 789.432 400.920 ;
    END
  END op_in[213]
  PIN op_in[214]
    DIRECTION INPUT ;
    USE SIGNAL ;
    SHAPE ABUTMENT ;
    PORT
      LAYER M4 ;
      RECT 789.240 402.768 789.432 402.792 ;
    END
  END op_in[214]
  PIN op_in[215]
    DIRECTION INPUT ;
    USE SIGNAL ;
    SHAPE ABUTMENT ;
    PORT
      LAYER M4 ;
      RECT 789.240 404.640 789.432 404.664 ;
    END
  END op_in[215]
  PIN op_in[216]
    DIRECTION INPUT ;
    USE SIGNAL ;
    SHAPE ABUTMENT ;
    PORT
      LAYER M4 ;
      RECT 789.240 406.512 789.432 406.536 ;
    END
  END op_in[216]
  PIN op_in[217]
    DIRECTION INPUT ;
    USE SIGNAL ;
    SHAPE ABUTMENT ;
    PORT
      LAYER M4 ;
      RECT 789.240 408.432 789.432 408.456 ;
    END
  END op_in[217]
  PIN op_in[218]
    DIRECTION INPUT ;
    USE SIGNAL ;
    SHAPE ABUTMENT ;
    PORT
      LAYER M4 ;
      RECT 789.240 410.304 789.432 410.328 ;
    END
  END op_in[218]
  PIN op_in[219]
    DIRECTION INPUT ;
    USE SIGNAL ;
    SHAPE ABUTMENT ;
    PORT
      LAYER M4 ;
      RECT 789.240 412.176 789.432 412.200 ;
    END
  END op_in[219]
  PIN op_in[220]
    DIRECTION INPUT ;
    USE SIGNAL ;
    SHAPE ABUTMENT ;
    PORT
      LAYER M4 ;
      RECT 789.240 414.048 789.432 414.072 ;
    END
  END op_in[220]
  PIN op_in[221]
    DIRECTION INPUT ;
    USE SIGNAL ;
    SHAPE ABUTMENT ;
    PORT
      LAYER M4 ;
      RECT 789.240 415.920 789.432 415.944 ;
    END
  END op_in[221]
  PIN op_in[222]
    DIRECTION INPUT ;
    USE SIGNAL ;
    SHAPE ABUTMENT ;
    PORT
      LAYER M4 ;
      RECT 789.240 417.792 789.432 417.816 ;
    END
  END op_in[222]
  PIN op_in[223]
    DIRECTION INPUT ;
    USE SIGNAL ;
    SHAPE ABUTMENT ;
    PORT
      LAYER M4 ;
      RECT 789.240 419.712 789.432 419.736 ;
    END
  END op_in[223]
  PIN op_in[224]
    DIRECTION INPUT ;
    USE SIGNAL ;
    SHAPE ABUTMENT ;
    PORT
      LAYER M4 ;
      RECT 789.240 421.584 789.432 421.608 ;
    END
  END op_in[224]
  PIN op_in[225]
    DIRECTION INPUT ;
    USE SIGNAL ;
    SHAPE ABUTMENT ;
    PORT
      LAYER M4 ;
      RECT 789.240 423.456 789.432 423.480 ;
    END
  END op_in[225]
  PIN op_in[226]
    DIRECTION INPUT ;
    USE SIGNAL ;
    SHAPE ABUTMENT ;
    PORT
      LAYER M4 ;
      RECT 789.240 425.328 789.432 425.352 ;
    END
  END op_in[226]
  PIN op_in[227]
    DIRECTION INPUT ;
    USE SIGNAL ;
    SHAPE ABUTMENT ;
    PORT
      LAYER M4 ;
      RECT 789.240 427.200 789.432 427.224 ;
    END
  END op_in[227]
  PIN op_in[228]
    DIRECTION INPUT ;
    USE SIGNAL ;
    SHAPE ABUTMENT ;
    PORT
      LAYER M4 ;
      RECT 789.240 429.072 789.432 429.096 ;
    END
  END op_in[228]
  PIN op_in[229]
    DIRECTION INPUT ;
    USE SIGNAL ;
    SHAPE ABUTMENT ;
    PORT
      LAYER M4 ;
      RECT 789.240 430.944 789.432 430.968 ;
    END
  END op_in[229]
  PIN op_in[230]
    DIRECTION INPUT ;
    USE SIGNAL ;
    SHAPE ABUTMENT ;
    PORT
      LAYER M4 ;
      RECT 789.240 432.864 789.432 432.888 ;
    END
  END op_in[230]
  PIN op_in[231]
    DIRECTION INPUT ;
    USE SIGNAL ;
    SHAPE ABUTMENT ;
    PORT
      LAYER M4 ;
      RECT 789.240 434.736 789.432 434.760 ;
    END
  END op_in[231]
  PIN op_in[232]
    DIRECTION INPUT ;
    USE SIGNAL ;
    SHAPE ABUTMENT ;
    PORT
      LAYER M4 ;
      RECT 789.240 436.608 789.432 436.632 ;
    END
  END op_in[232]
  PIN op_in[233]
    DIRECTION INPUT ;
    USE SIGNAL ;
    SHAPE ABUTMENT ;
    PORT
      LAYER M4 ;
      RECT 789.240 438.480 789.432 438.504 ;
    END
  END op_in[233]
  PIN op_in[234]
    DIRECTION INPUT ;
    USE SIGNAL ;
    SHAPE ABUTMENT ;
    PORT
      LAYER M4 ;
      RECT 789.240 440.352 789.432 440.376 ;
    END
  END op_in[234]
  PIN op_in[235]
    DIRECTION INPUT ;
    USE SIGNAL ;
    SHAPE ABUTMENT ;
    PORT
      LAYER M4 ;
      RECT 789.240 442.224 789.432 442.248 ;
    END
  END op_in[235]
  PIN op_in[236]
    DIRECTION INPUT ;
    USE SIGNAL ;
    SHAPE ABUTMENT ;
    PORT
      LAYER M4 ;
      RECT 789.240 444.144 789.432 444.168 ;
    END
  END op_in[236]
  PIN op_in[237]
    DIRECTION INPUT ;
    USE SIGNAL ;
    SHAPE ABUTMENT ;
    PORT
      LAYER M4 ;
      RECT 789.240 446.016 789.432 446.040 ;
    END
  END op_in[237]
  PIN op_in[238]
    DIRECTION INPUT ;
    USE SIGNAL ;
    SHAPE ABUTMENT ;
    PORT
      LAYER M4 ;
      RECT 789.240 447.888 789.432 447.912 ;
    END
  END op_in[238]
  PIN op_in[239]
    DIRECTION INPUT ;
    USE SIGNAL ;
    SHAPE ABUTMENT ;
    PORT
      LAYER M4 ;
      RECT 789.240 449.760 789.432 449.784 ;
    END
  END op_in[239]
  PIN op_in[240]
    DIRECTION INPUT ;
    USE SIGNAL ;
    SHAPE ABUTMENT ;
    PORT
      LAYER M4 ;
      RECT 789.240 451.632 789.432 451.656 ;
    END
  END op_in[240]
  PIN op_in[241]
    DIRECTION INPUT ;
    USE SIGNAL ;
    SHAPE ABUTMENT ;
    PORT
      LAYER M4 ;
      RECT 789.240 453.504 789.432 453.528 ;
    END
  END op_in[241]
  PIN op_in[242]
    DIRECTION INPUT ;
    USE SIGNAL ;
    SHAPE ABUTMENT ;
    PORT
      LAYER M4 ;
      RECT 789.240 455.424 789.432 455.448 ;
    END
  END op_in[242]
  PIN op_in[243]
    DIRECTION INPUT ;
    USE SIGNAL ;
    SHAPE ABUTMENT ;
    PORT
      LAYER M4 ;
      RECT 789.240 457.296 789.432 457.320 ;
    END
  END op_in[243]
  PIN op_in[244]
    DIRECTION INPUT ;
    USE SIGNAL ;
    SHAPE ABUTMENT ;
    PORT
      LAYER M4 ;
      RECT 789.240 459.168 789.432 459.192 ;
    END
  END op_in[244]
  PIN op_in[245]
    DIRECTION INPUT ;
    USE SIGNAL ;
    SHAPE ABUTMENT ;
    PORT
      LAYER M4 ;
      RECT 789.240 461.040 789.432 461.064 ;
    END
  END op_in[245]
  PIN op_in[246]
    DIRECTION INPUT ;
    USE SIGNAL ;
    SHAPE ABUTMENT ;
    PORT
      LAYER M4 ;
      RECT 789.240 462.912 789.432 462.936 ;
    END
  END op_in[246]
  PIN op_in[247]
    DIRECTION INPUT ;
    USE SIGNAL ;
    SHAPE ABUTMENT ;
    PORT
      LAYER M4 ;
      RECT 789.240 464.784 789.432 464.808 ;
    END
  END op_in[247]
  PIN op_in[248]
    DIRECTION INPUT ;
    USE SIGNAL ;
    SHAPE ABUTMENT ;
    PORT
      LAYER M4 ;
      RECT 789.240 466.704 789.432 466.728 ;
    END
  END op_in[248]
  PIN op_in[249]
    DIRECTION INPUT ;
    USE SIGNAL ;
    SHAPE ABUTMENT ;
    PORT
      LAYER M4 ;
      RECT 789.240 468.576 789.432 468.600 ;
    END
  END op_in[249]
  PIN op_in[250]
    DIRECTION INPUT ;
    USE SIGNAL ;
    SHAPE ABUTMENT ;
    PORT
      LAYER M4 ;
      RECT 789.240 470.448 789.432 470.472 ;
    END
  END op_in[250]
  PIN op_in[251]
    DIRECTION INPUT ;
    USE SIGNAL ;
    SHAPE ABUTMENT ;
    PORT
      LAYER M4 ;
      RECT 789.240 472.320 789.432 472.344 ;
    END
  END op_in[251]
  PIN op_in[252]
    DIRECTION INPUT ;
    USE SIGNAL ;
    SHAPE ABUTMENT ;
    PORT
      LAYER M4 ;
      RECT 789.240 474.192 789.432 474.216 ;
    END
  END op_in[252]
  PIN op_in[253]
    DIRECTION INPUT ;
    USE SIGNAL ;
    SHAPE ABUTMENT ;
    PORT
      LAYER M4 ;
      RECT 789.240 476.064 789.432 476.088 ;
    END
  END op_in[253]
  PIN op_in[254]
    DIRECTION INPUT ;
    USE SIGNAL ;
    SHAPE ABUTMENT ;
    PORT
      LAYER M4 ;
      RECT 789.240 477.984 789.432 478.008 ;
    END
  END op_in[254]
  PIN op_in[255]
    DIRECTION INPUT ;
    USE SIGNAL ;
    SHAPE ABUTMENT ;
    PORT
      LAYER M4 ;
      RECT 789.240 479.856 789.432 479.880 ;
    END
  END op_in[255]
  PIN op_in[256]
    DIRECTION INPUT ;
    USE SIGNAL ;
    SHAPE ABUTMENT ;
    PORT
      LAYER M4 ;
      RECT 789.240 481.728 789.432 481.752 ;
    END
  END op_in[256]
  PIN op_in[257]
    DIRECTION INPUT ;
    USE SIGNAL ;
    SHAPE ABUTMENT ;
    PORT
      LAYER M4 ;
      RECT 789.240 483.600 789.432 483.624 ;
    END
  END op_in[257]
  PIN op_in[258]
    DIRECTION INPUT ;
    USE SIGNAL ;
    SHAPE ABUTMENT ;
    PORT
      LAYER M4 ;
      RECT 789.240 485.472 789.432 485.496 ;
    END
  END op_in[258]
  PIN op_in[259]
    DIRECTION INPUT ;
    USE SIGNAL ;
    SHAPE ABUTMENT ;
    PORT
      LAYER M4 ;
      RECT 789.240 487.344 789.432 487.368 ;
    END
  END op_in[259]
  PIN op_in[260]
    DIRECTION INPUT ;
    USE SIGNAL ;
    SHAPE ABUTMENT ;
    PORT
      LAYER M4 ;
      RECT 789.240 489.264 789.432 489.288 ;
    END
  END op_in[260]
  PIN op_in[261]
    DIRECTION INPUT ;
    USE SIGNAL ;
    SHAPE ABUTMENT ;
    PORT
      LAYER M4 ;
      RECT 789.240 491.136 789.432 491.160 ;
    END
  END op_in[261]
  PIN op_in[262]
    DIRECTION INPUT ;
    USE SIGNAL ;
    SHAPE ABUTMENT ;
    PORT
      LAYER M4 ;
      RECT 789.240 493.008 789.432 493.032 ;
    END
  END op_in[262]
  PIN op_in[263]
    DIRECTION INPUT ;
    USE SIGNAL ;
    SHAPE ABUTMENT ;
    PORT
      LAYER M4 ;
      RECT 789.240 494.880 789.432 494.904 ;
    END
  END op_in[263]
  PIN op_in[264]
    DIRECTION INPUT ;
    USE SIGNAL ;
    SHAPE ABUTMENT ;
    PORT
      LAYER M4 ;
      RECT 789.240 496.752 789.432 496.776 ;
    END
  END op_in[264]
  PIN op_in[265]
    DIRECTION INPUT ;
    USE SIGNAL ;
    SHAPE ABUTMENT ;
    PORT
      LAYER M4 ;
      RECT 789.240 498.624 789.432 498.648 ;
    END
  END op_in[265]
  PIN op_in[266]
    DIRECTION INPUT ;
    USE SIGNAL ;
    SHAPE ABUTMENT ;
    PORT
      LAYER M4 ;
      RECT 789.240 500.496 789.432 500.520 ;
    END
  END op_in[266]
  PIN op_in[267]
    DIRECTION INPUT ;
    USE SIGNAL ;
    SHAPE ABUTMENT ;
    PORT
      LAYER M4 ;
      RECT 789.240 502.416 789.432 502.440 ;
    END
  END op_in[267]
  PIN op_in[268]
    DIRECTION INPUT ;
    USE SIGNAL ;
    SHAPE ABUTMENT ;
    PORT
      LAYER M4 ;
      RECT 789.240 504.288 789.432 504.312 ;
    END
  END op_in[268]
  PIN op_in[269]
    DIRECTION INPUT ;
    USE SIGNAL ;
    SHAPE ABUTMENT ;
    PORT
      LAYER M4 ;
      RECT 789.240 506.160 789.432 506.184 ;
    END
  END op_in[269]
  PIN op_in[270]
    DIRECTION INPUT ;
    USE SIGNAL ;
    SHAPE ABUTMENT ;
    PORT
      LAYER M4 ;
      RECT 789.240 508.032 789.432 508.056 ;
    END
  END op_in[270]
  PIN op_in[271]
    DIRECTION INPUT ;
    USE SIGNAL ;
    SHAPE ABUTMENT ;
    PORT
      LAYER M4 ;
      RECT 789.240 509.904 789.432 509.928 ;
    END
  END op_in[271]
  PIN op_in[272]
    DIRECTION INPUT ;
    USE SIGNAL ;
    SHAPE ABUTMENT ;
    PORT
      LAYER M4 ;
      RECT 789.240 511.776 789.432 511.800 ;
    END
  END op_in[272]
  PIN op_in[273]
    DIRECTION INPUT ;
    USE SIGNAL ;
    SHAPE ABUTMENT ;
    PORT
      LAYER M4 ;
      RECT 789.240 513.696 789.432 513.720 ;
    END
  END op_in[273]
  PIN op_in[274]
    DIRECTION INPUT ;
    USE SIGNAL ;
    SHAPE ABUTMENT ;
    PORT
      LAYER M4 ;
      RECT 789.240 515.568 789.432 515.592 ;
    END
  END op_in[274]
  PIN op_in[275]
    DIRECTION INPUT ;
    USE SIGNAL ;
    SHAPE ABUTMENT ;
    PORT
      LAYER M4 ;
      RECT 789.240 517.440 789.432 517.464 ;
    END
  END op_in[275]
  PIN op_in[276]
    DIRECTION INPUT ;
    USE SIGNAL ;
    SHAPE ABUTMENT ;
    PORT
      LAYER M4 ;
      RECT 789.240 519.312 789.432 519.336 ;
    END
  END op_in[276]
  PIN op_in[277]
    DIRECTION INPUT ;
    USE SIGNAL ;
    SHAPE ABUTMENT ;
    PORT
      LAYER M4 ;
      RECT 789.240 521.184 789.432 521.208 ;
    END
  END op_in[277]
  PIN op_in[278]
    DIRECTION INPUT ;
    USE SIGNAL ;
    SHAPE ABUTMENT ;
    PORT
      LAYER M4 ;
      RECT 789.240 523.056 789.432 523.080 ;
    END
  END op_in[278]
  PIN op_in[279]
    DIRECTION INPUT ;
    USE SIGNAL ;
    SHAPE ABUTMENT ;
    PORT
      LAYER M4 ;
      RECT 789.240 524.976 789.432 525.000 ;
    END
  END op_in[279]
  PIN op_in[280]
    DIRECTION INPUT ;
    USE SIGNAL ;
    SHAPE ABUTMENT ;
    PORT
      LAYER M4 ;
      RECT 789.240 526.848 789.432 526.872 ;
    END
  END op_in[280]
  PIN op_in[281]
    DIRECTION INPUT ;
    USE SIGNAL ;
    SHAPE ABUTMENT ;
    PORT
      LAYER M4 ;
      RECT 789.240 528.720 789.432 528.744 ;
    END
  END op_in[281]
  PIN op_in[282]
    DIRECTION INPUT ;
    USE SIGNAL ;
    SHAPE ABUTMENT ;
    PORT
      LAYER M4 ;
      RECT 789.240 530.592 789.432 530.616 ;
    END
  END op_in[282]
  PIN op_in[283]
    DIRECTION INPUT ;
    USE SIGNAL ;
    SHAPE ABUTMENT ;
    PORT
      LAYER M4 ;
      RECT 789.240 532.464 789.432 532.488 ;
    END
  END op_in[283]
  PIN op_in[284]
    DIRECTION INPUT ;
    USE SIGNAL ;
    SHAPE ABUTMENT ;
    PORT
      LAYER M4 ;
      RECT 789.240 534.336 789.432 534.360 ;
    END
  END op_in[284]
  PIN op_in[285]
    DIRECTION INPUT ;
    USE SIGNAL ;
    SHAPE ABUTMENT ;
    PORT
      LAYER M4 ;
      RECT 789.240 536.256 789.432 536.280 ;
    END
  END op_in[285]
  PIN op_in[286]
    DIRECTION INPUT ;
    USE SIGNAL ;
    SHAPE ABUTMENT ;
    PORT
      LAYER M4 ;
      RECT 789.240 538.128 789.432 538.152 ;
    END
  END op_in[286]
  PIN op_in[287]
    DIRECTION INPUT ;
    USE SIGNAL ;
    SHAPE ABUTMENT ;
    PORT
      LAYER M4 ;
      RECT 789.240 540.000 789.432 540.024 ;
    END
  END op_in[287]
  PIN op_in[288]
    DIRECTION INPUT ;
    USE SIGNAL ;
    SHAPE ABUTMENT ;
    PORT
      LAYER M4 ;
      RECT 789.240 541.872 789.432 541.896 ;
    END
  END op_in[288]
  PIN op_in[289]
    DIRECTION INPUT ;
    USE SIGNAL ;
    SHAPE ABUTMENT ;
    PORT
      LAYER M4 ;
      RECT 789.240 543.744 789.432 543.768 ;
    END
  END op_in[289]
  PIN op_in[290]
    DIRECTION INPUT ;
    USE SIGNAL ;
    SHAPE ABUTMENT ;
    PORT
      LAYER M4 ;
      RECT 789.240 545.616 789.432 545.640 ;
    END
  END op_in[290]
  PIN op_in[291]
    DIRECTION INPUT ;
    USE SIGNAL ;
    SHAPE ABUTMENT ;
    PORT
      LAYER M4 ;
      RECT 789.240 547.536 789.432 547.560 ;
    END
  END op_in[291]
  PIN op_in[292]
    DIRECTION INPUT ;
    USE SIGNAL ;
    SHAPE ABUTMENT ;
    PORT
      LAYER M4 ;
      RECT 789.240 549.408 789.432 549.432 ;
    END
  END op_in[292]
  PIN op_in[293]
    DIRECTION INPUT ;
    USE SIGNAL ;
    SHAPE ABUTMENT ;
    PORT
      LAYER M4 ;
      RECT 789.240 551.280 789.432 551.304 ;
    END
  END op_in[293]
  PIN op_in[294]
    DIRECTION INPUT ;
    USE SIGNAL ;
    SHAPE ABUTMENT ;
    PORT
      LAYER M4 ;
      RECT 789.240 553.152 789.432 553.176 ;
    END
  END op_in[294]
  PIN op_in[295]
    DIRECTION INPUT ;
    USE SIGNAL ;
    SHAPE ABUTMENT ;
    PORT
      LAYER M4 ;
      RECT 789.240 555.024 789.432 555.048 ;
    END
  END op_in[295]
  PIN op_in[296]
    DIRECTION INPUT ;
    USE SIGNAL ;
    SHAPE ABUTMENT ;
    PORT
      LAYER M4 ;
      RECT 789.240 556.896 789.432 556.920 ;
    END
  END op_in[296]
  PIN op_in[297]
    DIRECTION INPUT ;
    USE SIGNAL ;
    SHAPE ABUTMENT ;
    PORT
      LAYER M4 ;
      RECT 789.240 558.768 789.432 558.792 ;
    END
  END op_in[297]
  PIN op_in[298]
    DIRECTION INPUT ;
    USE SIGNAL ;
    SHAPE ABUTMENT ;
    PORT
      LAYER M4 ;
      RECT 789.240 560.688 789.432 560.712 ;
    END
  END op_in[298]
  PIN op_in[299]
    DIRECTION INPUT ;
    USE SIGNAL ;
    SHAPE ABUTMENT ;
    PORT
      LAYER M4 ;
      RECT 789.240 562.560 789.432 562.584 ;
    END
  END op_in[299]
  PIN op_in[300]
    DIRECTION INPUT ;
    USE SIGNAL ;
    SHAPE ABUTMENT ;
    PORT
      LAYER M4 ;
      RECT 789.240 564.432 789.432 564.456 ;
    END
  END op_in[300]
  PIN op_in[301]
    DIRECTION INPUT ;
    USE SIGNAL ;
    SHAPE ABUTMENT ;
    PORT
      LAYER M4 ;
      RECT 789.240 566.304 789.432 566.328 ;
    END
  END op_in[301]
  PIN op_in[302]
    DIRECTION INPUT ;
    USE SIGNAL ;
    SHAPE ABUTMENT ;
    PORT
      LAYER M4 ;
      RECT 789.240 568.176 789.432 568.200 ;
    END
  END op_in[302]
  PIN op_in[303]
    DIRECTION INPUT ;
    USE SIGNAL ;
    SHAPE ABUTMENT ;
    PORT
      LAYER M4 ;
      RECT 789.240 570.048 789.432 570.072 ;
    END
  END op_in[303]
  PIN op_in[304]
    DIRECTION INPUT ;
    USE SIGNAL ;
    SHAPE ABUTMENT ;
    PORT
      LAYER M4 ;
      RECT 789.240 571.968 789.432 571.992 ;
    END
  END op_in[304]
  PIN op_in[305]
    DIRECTION INPUT ;
    USE SIGNAL ;
    SHAPE ABUTMENT ;
    PORT
      LAYER M4 ;
      RECT 789.240 573.840 789.432 573.864 ;
    END
  END op_in[305]
  PIN op_in[306]
    DIRECTION INPUT ;
    USE SIGNAL ;
    SHAPE ABUTMENT ;
    PORT
      LAYER M4 ;
      RECT 789.240 575.712 789.432 575.736 ;
    END
  END op_in[306]
  PIN op_in[307]
    DIRECTION INPUT ;
    USE SIGNAL ;
    SHAPE ABUTMENT ;
    PORT
      LAYER M4 ;
      RECT 789.240 577.584 789.432 577.608 ;
    END
  END op_in[307]
  PIN op_in[308]
    DIRECTION INPUT ;
    USE SIGNAL ;
    SHAPE ABUTMENT ;
    PORT
      LAYER M4 ;
      RECT 789.240 579.456 789.432 579.480 ;
    END
  END op_in[308]
  PIN op_in[309]
    DIRECTION INPUT ;
    USE SIGNAL ;
    SHAPE ABUTMENT ;
    PORT
      LAYER M4 ;
      RECT 789.240 581.328 789.432 581.352 ;
    END
  END op_in[309]
  PIN op_in[310]
    DIRECTION INPUT ;
    USE SIGNAL ;
    SHAPE ABUTMENT ;
    PORT
      LAYER M4 ;
      RECT 789.240 583.248 789.432 583.272 ;
    END
  END op_in[310]
  PIN op_in[311]
    DIRECTION INPUT ;
    USE SIGNAL ;
    SHAPE ABUTMENT ;
    PORT
      LAYER M4 ;
      RECT 789.240 585.120 789.432 585.144 ;
    END
  END op_in[311]
  PIN op_in[312]
    DIRECTION INPUT ;
    USE SIGNAL ;
    SHAPE ABUTMENT ;
    PORT
      LAYER M4 ;
      RECT 789.240 586.992 789.432 587.016 ;
    END
  END op_in[312]
  PIN op_in[313]
    DIRECTION INPUT ;
    USE SIGNAL ;
    SHAPE ABUTMENT ;
    PORT
      LAYER M4 ;
      RECT 789.240 588.864 789.432 588.888 ;
    END
  END op_in[313]
  PIN op_in[314]
    DIRECTION INPUT ;
    USE SIGNAL ;
    SHAPE ABUTMENT ;
    PORT
      LAYER M4 ;
      RECT 789.240 590.736 789.432 590.760 ;
    END
  END op_in[314]
  PIN op_in[315]
    DIRECTION INPUT ;
    USE SIGNAL ;
    SHAPE ABUTMENT ;
    PORT
      LAYER M4 ;
      RECT 789.240 592.608 789.432 592.632 ;
    END
  END op_in[315]
  PIN op_in[316]
    DIRECTION INPUT ;
    USE SIGNAL ;
    SHAPE ABUTMENT ;
    PORT
      LAYER M4 ;
      RECT 789.240 594.528 789.432 594.552 ;
    END
  END op_in[316]
  PIN op_in[317]
    DIRECTION INPUT ;
    USE SIGNAL ;
    SHAPE ABUTMENT ;
    PORT
      LAYER M4 ;
      RECT 789.240 596.400 789.432 596.424 ;
    END
  END op_in[317]
  PIN op_in[318]
    DIRECTION INPUT ;
    USE SIGNAL ;
    SHAPE ABUTMENT ;
    PORT
      LAYER M4 ;
      RECT 789.240 598.272 789.432 598.296 ;
    END
  END op_in[318]
  PIN op_in[319]
    DIRECTION INPUT ;
    USE SIGNAL ;
    SHAPE ABUTMENT ;
    PORT
      LAYER M4 ;
      RECT 789.240 600.144 789.432 600.168 ;
    END
  END op_in[319]
  PIN op_in[320]
    DIRECTION INPUT ;
    USE SIGNAL ;
    SHAPE ABUTMENT ;
    PORT
      LAYER M4 ;
      RECT 789.240 602.016 789.432 602.040 ;
    END
  END op_in[320]
  PIN op_in[321]
    DIRECTION INPUT ;
    USE SIGNAL ;
    SHAPE ABUTMENT ;
    PORT
      LAYER M4 ;
      RECT 789.240 603.888 789.432 603.912 ;
    END
  END op_in[321]
  PIN op_in[322]
    DIRECTION INPUT ;
    USE SIGNAL ;
    SHAPE ABUTMENT ;
    PORT
      LAYER M4 ;
      RECT 789.240 605.808 789.432 605.832 ;
    END
  END op_in[322]
  PIN op_in[323]
    DIRECTION INPUT ;
    USE SIGNAL ;
    SHAPE ABUTMENT ;
    PORT
      LAYER M4 ;
      RECT 789.240 607.680 789.432 607.704 ;
    END
  END op_in[323]
  PIN op_in[324]
    DIRECTION INPUT ;
    USE SIGNAL ;
    SHAPE ABUTMENT ;
    PORT
      LAYER M4 ;
      RECT 789.240 609.552 789.432 609.576 ;
    END
  END op_in[324]
  PIN op_in[325]
    DIRECTION INPUT ;
    USE SIGNAL ;
    SHAPE ABUTMENT ;
    PORT
      LAYER M4 ;
      RECT 789.240 611.424 789.432 611.448 ;
    END
  END op_in[325]
  PIN op_in[326]
    DIRECTION INPUT ;
    USE SIGNAL ;
    SHAPE ABUTMENT ;
    PORT
      LAYER M4 ;
      RECT 789.240 613.296 789.432 613.320 ;
    END
  END op_in[326]
  PIN op_in[327]
    DIRECTION INPUT ;
    USE SIGNAL ;
    SHAPE ABUTMENT ;
    PORT
      LAYER M4 ;
      RECT 789.240 615.168 789.432 615.192 ;
    END
  END op_in[327]
  PIN op_in[328]
    DIRECTION INPUT ;
    USE SIGNAL ;
    SHAPE ABUTMENT ;
    PORT
      LAYER M4 ;
      RECT 789.240 617.040 789.432 617.064 ;
    END
  END op_in[328]
  PIN op_in[329]
    DIRECTION INPUT ;
    USE SIGNAL ;
    SHAPE ABUTMENT ;
    PORT
      LAYER M4 ;
      RECT 789.240 618.960 789.432 618.984 ;
    END
  END op_in[329]
  PIN op_in[330]
    DIRECTION INPUT ;
    USE SIGNAL ;
    SHAPE ABUTMENT ;
    PORT
      LAYER M4 ;
      RECT 789.240 620.832 789.432 620.856 ;
    END
  END op_in[330]
  PIN op_in[331]
    DIRECTION INPUT ;
    USE SIGNAL ;
    SHAPE ABUTMENT ;
    PORT
      LAYER M4 ;
      RECT 789.240 622.704 789.432 622.728 ;
    END
  END op_in[331]
  PIN op_in[332]
    DIRECTION INPUT ;
    USE SIGNAL ;
    SHAPE ABUTMENT ;
    PORT
      LAYER M4 ;
      RECT 789.240 624.576 789.432 624.600 ;
    END
  END op_in[332]
  PIN op_in[333]
    DIRECTION INPUT ;
    USE SIGNAL ;
    SHAPE ABUTMENT ;
    PORT
      LAYER M4 ;
      RECT 789.240 626.448 789.432 626.472 ;
    END
  END op_in[333]
  PIN op_in[334]
    DIRECTION INPUT ;
    USE SIGNAL ;
    SHAPE ABUTMENT ;
    PORT
      LAYER M4 ;
      RECT 789.240 628.320 789.432 628.344 ;
    END
  END op_in[334]
  PIN op_in[335]
    DIRECTION INPUT ;
    USE SIGNAL ;
    SHAPE ABUTMENT ;
    PORT
      LAYER M4 ;
      RECT 789.240 630.240 789.432 630.264 ;
    END
  END op_in[335]
  PIN op_in[336]
    DIRECTION INPUT ;
    USE SIGNAL ;
    SHAPE ABUTMENT ;
    PORT
      LAYER M4 ;
      RECT 789.240 632.112 789.432 632.136 ;
    END
  END op_in[336]
  PIN op_in[337]
    DIRECTION INPUT ;
    USE SIGNAL ;
    SHAPE ABUTMENT ;
    PORT
      LAYER M4 ;
      RECT 789.240 633.984 789.432 634.008 ;
    END
  END op_in[337]
  PIN op_in[338]
    DIRECTION INPUT ;
    USE SIGNAL ;
    SHAPE ABUTMENT ;
    PORT
      LAYER M4 ;
      RECT 789.240 635.856 789.432 635.880 ;
    END
  END op_in[338]
  PIN op_in[339]
    DIRECTION INPUT ;
    USE SIGNAL ;
    SHAPE ABUTMENT ;
    PORT
      LAYER M4 ;
      RECT 789.240 637.728 789.432 637.752 ;
    END
  END op_in[339]
  PIN op_in[340]
    DIRECTION INPUT ;
    USE SIGNAL ;
    SHAPE ABUTMENT ;
    PORT
      LAYER M4 ;
      RECT 789.240 639.600 789.432 639.624 ;
    END
  END op_in[340]
  PIN op_in[341]
    DIRECTION INPUT ;
    USE SIGNAL ;
    SHAPE ABUTMENT ;
    PORT
      LAYER M4 ;
      RECT 789.240 641.520 789.432 641.544 ;
    END
  END op_in[341]
  PIN op_in[342]
    DIRECTION INPUT ;
    USE SIGNAL ;
    SHAPE ABUTMENT ;
    PORT
      LAYER M4 ;
      RECT 789.240 643.392 789.432 643.416 ;
    END
  END op_in[342]
  PIN op_in[343]
    DIRECTION INPUT ;
    USE SIGNAL ;
    SHAPE ABUTMENT ;
    PORT
      LAYER M4 ;
      RECT 789.240 645.264 789.432 645.288 ;
    END
  END op_in[343]
  PIN op_in[344]
    DIRECTION INPUT ;
    USE SIGNAL ;
    SHAPE ABUTMENT ;
    PORT
      LAYER M4 ;
      RECT 789.240 647.136 789.432 647.160 ;
    END
  END op_in[344]
  PIN op_in[345]
    DIRECTION INPUT ;
    USE SIGNAL ;
    SHAPE ABUTMENT ;
    PORT
      LAYER M4 ;
      RECT 789.240 649.008 789.432 649.032 ;
    END
  END op_in[345]
  PIN op_in[346]
    DIRECTION INPUT ;
    USE SIGNAL ;
    SHAPE ABUTMENT ;
    PORT
      LAYER M4 ;
      RECT 789.240 650.880 789.432 650.904 ;
    END
  END op_in[346]
  PIN op_in[347]
    DIRECTION INPUT ;
    USE SIGNAL ;
    SHAPE ABUTMENT ;
    PORT
      LAYER M4 ;
      RECT 789.240 652.800 789.432 652.824 ;
    END
  END op_in[347]
  PIN op_in[348]
    DIRECTION INPUT ;
    USE SIGNAL ;
    SHAPE ABUTMENT ;
    PORT
      LAYER M4 ;
      RECT 789.240 654.672 789.432 654.696 ;
    END
  END op_in[348]
  PIN op_in[349]
    DIRECTION INPUT ;
    USE SIGNAL ;
    SHAPE ABUTMENT ;
    PORT
      LAYER M4 ;
      RECT 789.240 656.544 789.432 656.568 ;
    END
  END op_in[349]
  PIN op_in[350]
    DIRECTION INPUT ;
    USE SIGNAL ;
    SHAPE ABUTMENT ;
    PORT
      LAYER M4 ;
      RECT 789.240 658.416 789.432 658.440 ;
    END
  END op_in[350]
  PIN op_in[351]
    DIRECTION INPUT ;
    USE SIGNAL ;
    SHAPE ABUTMENT ;
    PORT
      LAYER M4 ;
      RECT 789.240 660.288 789.432 660.312 ;
    END
  END op_in[351]
  PIN op_in[352]
    DIRECTION INPUT ;
    USE SIGNAL ;
    SHAPE ABUTMENT ;
    PORT
      LAYER M4 ;
      RECT 789.240 662.160 789.432 662.184 ;
    END
  END op_in[352]
  PIN op_in[353]
    DIRECTION INPUT ;
    USE SIGNAL ;
    SHAPE ABUTMENT ;
    PORT
      LAYER M4 ;
      RECT 789.240 664.080 789.432 664.104 ;
    END
  END op_in[353]
  PIN op_in[354]
    DIRECTION INPUT ;
    USE SIGNAL ;
    SHAPE ABUTMENT ;
    PORT
      LAYER M4 ;
      RECT 789.240 665.952 789.432 665.976 ;
    END
  END op_in[354]
  PIN op_in[355]
    DIRECTION INPUT ;
    USE SIGNAL ;
    SHAPE ABUTMENT ;
    PORT
      LAYER M4 ;
      RECT 789.240 667.824 789.432 667.848 ;
    END
  END op_in[355]
  PIN op_in[356]
    DIRECTION INPUT ;
    USE SIGNAL ;
    SHAPE ABUTMENT ;
    PORT
      LAYER M4 ;
      RECT 789.240 669.696 789.432 669.720 ;
    END
  END op_in[356]
  PIN op_in[357]
    DIRECTION INPUT ;
    USE SIGNAL ;
    SHAPE ABUTMENT ;
    PORT
      LAYER M4 ;
      RECT 789.240 671.568 789.432 671.592 ;
    END
  END op_in[357]
  PIN op_in[358]
    DIRECTION INPUT ;
    USE SIGNAL ;
    SHAPE ABUTMENT ;
    PORT
      LAYER M4 ;
      RECT 789.240 673.440 789.432 673.464 ;
    END
  END op_in[358]
  PIN op_in[359]
    DIRECTION INPUT ;
    USE SIGNAL ;
    SHAPE ABUTMENT ;
    PORT
      LAYER M4 ;
      RECT 789.240 675.312 789.432 675.336 ;
    END
  END op_in[359]
  PIN op_in[360]
    DIRECTION INPUT ;
    USE SIGNAL ;
    SHAPE ABUTMENT ;
    PORT
      LAYER M4 ;
      RECT 789.240 677.232 789.432 677.256 ;
    END
  END op_in[360]
  PIN op_in[361]
    DIRECTION INPUT ;
    USE SIGNAL ;
    SHAPE ABUTMENT ;
    PORT
      LAYER M4 ;
      RECT 789.240 679.104 789.432 679.128 ;
    END
  END op_in[361]
  PIN op_in[362]
    DIRECTION INPUT ;
    USE SIGNAL ;
    SHAPE ABUTMENT ;
    PORT
      LAYER M4 ;
      RECT 789.240 680.976 789.432 681.000 ;
    END
  END op_in[362]
  PIN op_in[363]
    DIRECTION INPUT ;
    USE SIGNAL ;
    SHAPE ABUTMENT ;
    PORT
      LAYER M4 ;
      RECT 789.240 682.848 789.432 682.872 ;
    END
  END op_in[363]
  PIN op_in[364]
    DIRECTION INPUT ;
    USE SIGNAL ;
    SHAPE ABUTMENT ;
    PORT
      LAYER M4 ;
      RECT 789.240 684.720 789.432 684.744 ;
    END
  END op_in[364]
  PIN op_in[365]
    DIRECTION INPUT ;
    USE SIGNAL ;
    SHAPE ABUTMENT ;
    PORT
      LAYER M4 ;
      RECT 789.240 686.592 789.432 686.616 ;
    END
  END op_in[365]
  PIN op_in[366]
    DIRECTION INPUT ;
    USE SIGNAL ;
    SHAPE ABUTMENT ;
    PORT
      LAYER M4 ;
      RECT 789.240 688.512 789.432 688.536 ;
    END
  END op_in[366]
  PIN op_in[367]
    DIRECTION INPUT ;
    USE SIGNAL ;
    SHAPE ABUTMENT ;
    PORT
      LAYER M4 ;
      RECT 789.240 690.384 789.432 690.408 ;
    END
  END op_in[367]
  PIN op_in[368]
    DIRECTION INPUT ;
    USE SIGNAL ;
    SHAPE ABUTMENT ;
    PORT
      LAYER M4 ;
      RECT 789.240 692.256 789.432 692.280 ;
    END
  END op_in[368]
  PIN op_in[369]
    DIRECTION INPUT ;
    USE SIGNAL ;
    SHAPE ABUTMENT ;
    PORT
      LAYER M4 ;
      RECT 789.240 694.128 789.432 694.152 ;
    END
  END op_in[369]
  PIN op_in[370]
    DIRECTION INPUT ;
    USE SIGNAL ;
    SHAPE ABUTMENT ;
    PORT
      LAYER M4 ;
      RECT 789.240 696.000 789.432 696.024 ;
    END
  END op_in[370]
  PIN op_in[371]
    DIRECTION INPUT ;
    USE SIGNAL ;
    SHAPE ABUTMENT ;
    PORT
      LAYER M4 ;
      RECT 789.240 697.872 789.432 697.896 ;
    END
  END op_in[371]
  PIN op_in[372]
    DIRECTION INPUT ;
    USE SIGNAL ;
    SHAPE ABUTMENT ;
    PORT
      LAYER M4 ;
      RECT 789.240 699.792 789.432 699.816 ;
    END
  END op_in[372]
  PIN op_in[373]
    DIRECTION INPUT ;
    USE SIGNAL ;
    SHAPE ABUTMENT ;
    PORT
      LAYER M4 ;
      RECT 789.240 701.664 789.432 701.688 ;
    END
  END op_in[373]
  PIN op_in[374]
    DIRECTION INPUT ;
    USE SIGNAL ;
    SHAPE ABUTMENT ;
    PORT
      LAYER M4 ;
      RECT 789.240 703.536 789.432 703.560 ;
    END
  END op_in[374]
  PIN op_in[375]
    DIRECTION INPUT ;
    USE SIGNAL ;
    SHAPE ABUTMENT ;
    PORT
      LAYER M4 ;
      RECT 789.240 705.408 789.432 705.432 ;
    END
  END op_in[375]
  PIN op_in[376]
    DIRECTION INPUT ;
    USE SIGNAL ;
    SHAPE ABUTMENT ;
    PORT
      LAYER M4 ;
      RECT 789.240 707.280 789.432 707.304 ;
    END
  END op_in[376]
  PIN op_in[377]
    DIRECTION INPUT ;
    USE SIGNAL ;
    SHAPE ABUTMENT ;
    PORT
      LAYER M4 ;
      RECT 789.240 709.152 789.432 709.176 ;
    END
  END op_in[377]
  PIN op_in[378]
    DIRECTION INPUT ;
    USE SIGNAL ;
    SHAPE ABUTMENT ;
    PORT
      LAYER M4 ;
      RECT 789.240 711.072 789.432 711.096 ;
    END
  END op_in[378]
  PIN op_in[379]
    DIRECTION INPUT ;
    USE SIGNAL ;
    SHAPE ABUTMENT ;
    PORT
      LAYER M4 ;
      RECT 789.240 712.944 789.432 712.968 ;
    END
  END op_in[379]
  PIN res_out[0]
    DIRECTION OUTPUT ;
    USE SIGNAL ;
    SHAPE ABUTMENT ;
    PORT
      LAYER M4 ;
      RECT 789.240 714.816 789.432 714.840 ;
    END
  END res_out[0]
  PIN res_out[1]
    DIRECTION OUTPUT ;
    USE SIGNAL ;
    SHAPE ABUTMENT ;
    PORT
      LAYER M4 ;
      RECT 789.240 716.688 789.432 716.712 ;
    END
  END res_out[1]
  PIN res_out[2]
    DIRECTION OUTPUT ;
    USE SIGNAL ;
    SHAPE ABUTMENT ;
    PORT
      LAYER M4 ;
      RECT 789.240 718.560 789.432 718.584 ;
    END
  END res_out[2]
  PIN res_out[3]
    DIRECTION OUTPUT ;
    USE SIGNAL ;
    SHAPE ABUTMENT ;
    PORT
      LAYER M4 ;
      RECT 789.240 720.432 789.432 720.456 ;
    END
  END res_out[3]
  PIN res_out[4]
    DIRECTION OUTPUT ;
    USE SIGNAL ;
    SHAPE ABUTMENT ;
    PORT
      LAYER M4 ;
      RECT 789.240 722.352 789.432 722.376 ;
    END
  END res_out[4]
  PIN res_out[5]
    DIRECTION OUTPUT ;
    USE SIGNAL ;
    SHAPE ABUTMENT ;
    PORT
      LAYER M4 ;
      RECT 789.240 724.224 789.432 724.248 ;
    END
  END res_out[5]
  PIN res_out[6]
    DIRECTION OUTPUT ;
    USE SIGNAL ;
    SHAPE ABUTMENT ;
    PORT
      LAYER M4 ;
      RECT 789.240 726.096 789.432 726.120 ;
    END
  END res_out[6]
  PIN res_out[7]
    DIRECTION OUTPUT ;
    USE SIGNAL ;
    SHAPE ABUTMENT ;
    PORT
      LAYER M4 ;
      RECT 789.240 727.968 789.432 727.992 ;
    END
  END res_out[7]
  PIN res_out[8]
    DIRECTION OUTPUT ;
    USE SIGNAL ;
    SHAPE ABUTMENT ;
    PORT
      LAYER M4 ;
      RECT 789.240 729.840 789.432 729.864 ;
    END
  END res_out[8]
  PIN res_out[9]
    DIRECTION OUTPUT ;
    USE SIGNAL ;
    SHAPE ABUTMENT ;
    PORT
      LAYER M4 ;
      RECT 789.240 731.712 789.432 731.736 ;
    END
  END res_out[9]
  PIN res_out[10]
    DIRECTION OUTPUT ;
    USE SIGNAL ;
    SHAPE ABUTMENT ;
    PORT
      LAYER M4 ;
      RECT 789.240 733.632 789.432 733.656 ;
    END
  END res_out[10]
  PIN res_out[11]
    DIRECTION OUTPUT ;
    USE SIGNAL ;
    SHAPE ABUTMENT ;
    PORT
      LAYER M4 ;
      RECT 789.240 735.504 789.432 735.528 ;
    END
  END res_out[11]
  PIN res_out[12]
    DIRECTION OUTPUT ;
    USE SIGNAL ;
    SHAPE ABUTMENT ;
    PORT
      LAYER M4 ;
      RECT 789.240 737.376 789.432 737.400 ;
    END
  END res_out[12]
  PIN res_out[13]
    DIRECTION OUTPUT ;
    USE SIGNAL ;
    SHAPE ABUTMENT ;
    PORT
      LAYER M4 ;
      RECT 789.240 739.248 789.432 739.272 ;
    END
  END res_out[13]
  PIN res_out[14]
    DIRECTION OUTPUT ;
    USE SIGNAL ;
    SHAPE ABUTMENT ;
    PORT
      LAYER M4 ;
      RECT 789.240 741.120 789.432 741.144 ;
    END
  END res_out[14]
  PIN res_out[15]
    DIRECTION OUTPUT ;
    USE SIGNAL ;
    SHAPE ABUTMENT ;
    PORT
      LAYER M4 ;
      RECT 789.240 742.992 789.432 743.016 ;
    END
  END res_out[15]
  PIN res_out[16]
    DIRECTION OUTPUT ;
    USE SIGNAL ;
    SHAPE ABUTMENT ;
    PORT
      LAYER M4 ;
      RECT 789.240 744.864 789.432 744.888 ;
    END
  END res_out[16]
  PIN res_out[17]
    DIRECTION OUTPUT ;
    USE SIGNAL ;
    SHAPE ABUTMENT ;
    PORT
      LAYER M4 ;
      RECT 789.240 746.784 789.432 746.808 ;
    END
  END res_out[17]
  PIN res_out[18]
    DIRECTION OUTPUT ;
    USE SIGNAL ;
    SHAPE ABUTMENT ;
    PORT
      LAYER M4 ;
      RECT 789.240 748.656 789.432 748.680 ;
    END
  END res_out[18]
  PIN res_out[19]
    DIRECTION OUTPUT ;
    USE SIGNAL ;
    SHAPE ABUTMENT ;
    PORT
      LAYER M4 ;
      RECT 789.240 750.528 789.432 750.552 ;
    END
  END res_out[19]
  PIN res_out[20]
    DIRECTION OUTPUT ;
    USE SIGNAL ;
    SHAPE ABUTMENT ;
    PORT
      LAYER M4 ;
      RECT 789.240 752.400 789.432 752.424 ;
    END
  END res_out[20]
  PIN res_out[21]
    DIRECTION OUTPUT ;
    USE SIGNAL ;
    SHAPE ABUTMENT ;
    PORT
      LAYER M4 ;
      RECT 789.240 754.272 789.432 754.296 ;
    END
  END res_out[21]
  PIN res_out[22]
    DIRECTION OUTPUT ;
    USE SIGNAL ;
    SHAPE ABUTMENT ;
    PORT
      LAYER M4 ;
      RECT 789.240 756.144 789.432 756.168 ;
    END
  END res_out[22]
  PIN res_out[23]
    DIRECTION OUTPUT ;
    USE SIGNAL ;
    SHAPE ABUTMENT ;
    PORT
      LAYER M4 ;
      RECT 789.240 758.064 789.432 758.088 ;
    END
  END res_out[23]
  PIN res_out[24]
    DIRECTION OUTPUT ;
    USE SIGNAL ;
    SHAPE ABUTMENT ;
    PORT
      LAYER M4 ;
      RECT 789.240 759.936 789.432 759.960 ;
    END
  END res_out[24]
  PIN res_out[25]
    DIRECTION OUTPUT ;
    USE SIGNAL ;
    SHAPE ABUTMENT ;
    PORT
      LAYER M4 ;
      RECT 789.240 761.808 789.432 761.832 ;
    END
  END res_out[25]
  PIN res_out[26]
    DIRECTION OUTPUT ;
    USE SIGNAL ;
    SHAPE ABUTMENT ;
    PORT
      LAYER M4 ;
      RECT 789.240 763.680 789.432 763.704 ;
    END
  END res_out[26]
  PIN res_out[27]
    DIRECTION OUTPUT ;
    USE SIGNAL ;
    SHAPE ABUTMENT ;
    PORT
      LAYER M4 ;
      RECT 789.240 765.552 789.432 765.576 ;
    END
  END res_out[27]
  PIN res_out[28]
    DIRECTION OUTPUT ;
    USE SIGNAL ;
    SHAPE ABUTMENT ;
    PORT
      LAYER M4 ;
      RECT 789.240 767.424 789.432 767.448 ;
    END
  END res_out[28]
  PIN res_out[29]
    DIRECTION OUTPUT ;
    USE SIGNAL ;
    SHAPE ABUTMENT ;
    PORT
      LAYER M4 ;
      RECT 789.240 769.344 789.432 769.368 ;
    END
  END res_out[29]
  PIN res_out[30]
    DIRECTION OUTPUT ;
    USE SIGNAL ;
    SHAPE ABUTMENT ;
    PORT
      LAYER M4 ;
      RECT 789.240 771.216 789.432 771.240 ;
    END
  END res_out[30]
  PIN res_out[31]
    DIRECTION OUTPUT ;
    USE SIGNAL ;
    SHAPE ABUTMENT ;
    PORT
      LAYER M4 ;
      RECT 789.240 773.088 789.432 773.112 ;
    END
  END res_out[31]
  PIN res_out[32]
    DIRECTION OUTPUT ;
    USE SIGNAL ;
    SHAPE ABUTMENT ;
    PORT
      LAYER M4 ;
      RECT 789.240 774.960 789.432 774.984 ;
    END
  END res_out[32]
  PIN res_out[33]
    DIRECTION OUTPUT ;
    USE SIGNAL ;
    SHAPE ABUTMENT ;
    PORT
      LAYER M4 ;
      RECT 789.240 776.832 789.432 776.856 ;
    END
  END res_out[33]
  PIN res_out[34]
    DIRECTION OUTPUT ;
    USE SIGNAL ;
    SHAPE ABUTMENT ;
    PORT
      LAYER M4 ;
      RECT 789.240 778.704 789.432 778.728 ;
    END
  END res_out[34]
  PIN res_out[35]
    DIRECTION OUTPUT ;
    USE SIGNAL ;
    SHAPE ABUTMENT ;
    PORT
      LAYER M4 ;
      RECT 789.240 780.624 789.432 780.648 ;
    END
  END res_out[35]
  PIN res_out[36]
    DIRECTION OUTPUT ;
    USE SIGNAL ;
    SHAPE ABUTMENT ;
    PORT
      LAYER M4 ;
      RECT 789.240 782.496 789.432 782.520 ;
    END
  END res_out[36]
  PIN res_out[37]
    DIRECTION OUTPUT ;
    USE SIGNAL ;
    SHAPE ABUTMENT ;
    PORT
      LAYER M4 ;
      RECT 789.240 784.368 789.432 784.392 ;
    END
  END res_out[37]
  PIN res_out[38]
    DIRECTION OUTPUT ;
    USE SIGNAL ;
    SHAPE ABUTMENT ;
    PORT
      LAYER M4 ;
      RECT 789.240 786.240 789.432 786.264 ;
    END
  END res_out[38]
  PIN res_out[39]
    DIRECTION OUTPUT ;
    USE SIGNAL ;
    SHAPE ABUTMENT ;
    PORT
      LAYER M4 ;
      RECT 789.240 788.112 789.432 788.136 ;
    END
  END res_out[39]
  PIN res_out[40]
    DIRECTION OUTPUT ;
    USE SIGNAL ;
    SHAPE ABUTMENT ;
    PORT
      LAYER M4 ;
      RECT 789.240 789.984 789.432 790.008 ;
    END
  END res_out[40]
  PIN res_out[41]
    DIRECTION OUTPUT ;
    USE SIGNAL ;
    SHAPE ABUTMENT ;
    PORT
      LAYER M4 ;
      RECT 789.240 791.904 789.432 791.928 ;
    END
  END res_out[41]
  PIN res_out[42]
    DIRECTION OUTPUT ;
    USE SIGNAL ;
    SHAPE ABUTMENT ;
    PORT
      LAYER M4 ;
      RECT 789.240 793.776 789.432 793.800 ;
    END
  END res_out[42]
  PIN res_out[43]
    DIRECTION OUTPUT ;
    USE SIGNAL ;
    SHAPE ABUTMENT ;
    PORT
      LAYER M4 ;
      RECT 789.240 795.648 789.432 795.672 ;
    END
  END res_out[43]
  PIN res_out[44]
    DIRECTION OUTPUT ;
    USE SIGNAL ;
    SHAPE ABUTMENT ;
    PORT
      LAYER M4 ;
      RECT 789.240 797.520 789.432 797.544 ;
    END
  END res_out[44]
  PIN res_out[45]
    DIRECTION OUTPUT ;
    USE SIGNAL ;
    SHAPE ABUTMENT ;
    PORT
      LAYER M4 ;
      RECT 789.240 799.392 789.432 799.416 ;
    END
  END res_out[45]
  PIN res_out[46]
    DIRECTION OUTPUT ;
    USE SIGNAL ;
    SHAPE ABUTMENT ;
    PORT
      LAYER M4 ;
      RECT 789.240 801.264 789.432 801.288 ;
    END
  END res_out[46]
  PIN res_out[47]
    DIRECTION OUTPUT ;
    USE SIGNAL ;
    SHAPE ABUTMENT ;
    PORT
      LAYER M4 ;
      RECT 789.240 803.136 789.432 803.160 ;
    END
  END res_out[47]
  PIN res_out[48]
    DIRECTION OUTPUT ;
    USE SIGNAL ;
    SHAPE ABUTMENT ;
    PORT
      LAYER M4 ;
      RECT 789.240 805.056 789.432 805.080 ;
    END
  END res_out[48]
  PIN res_out[49]
    DIRECTION OUTPUT ;
    USE SIGNAL ;
    SHAPE ABUTMENT ;
    PORT
      LAYER M4 ;
      RECT 789.240 806.928 789.432 806.952 ;
    END
  END res_out[49]
  PIN res_out[50]
    DIRECTION OUTPUT ;
    USE SIGNAL ;
    SHAPE ABUTMENT ;
    PORT
      LAYER M4 ;
      RECT 789.240 808.800 789.432 808.824 ;
    END
  END res_out[50]
  PIN res_out[51]
    DIRECTION OUTPUT ;
    USE SIGNAL ;
    SHAPE ABUTMENT ;
    PORT
      LAYER M4 ;
      RECT 789.240 810.672 789.432 810.696 ;
    END
  END res_out[51]
  PIN res_out[52]
    DIRECTION OUTPUT ;
    USE SIGNAL ;
    SHAPE ABUTMENT ;
    PORT
      LAYER M4 ;
      RECT 789.240 812.544 789.432 812.568 ;
    END
  END res_out[52]
  PIN res_out[53]
    DIRECTION OUTPUT ;
    USE SIGNAL ;
    SHAPE ABUTMENT ;
    PORT
      LAYER M4 ;
      RECT 789.240 814.416 789.432 814.440 ;
    END
  END res_out[53]
  PIN res_out[54]
    DIRECTION OUTPUT ;
    USE SIGNAL ;
    SHAPE ABUTMENT ;
    PORT
      LAYER M4 ;
      RECT 789.240 816.336 789.432 816.360 ;
    END
  END res_out[54]
  PIN res_out[55]
    DIRECTION OUTPUT ;
    USE SIGNAL ;
    SHAPE ABUTMENT ;
    PORT
      LAYER M4 ;
      RECT 789.240 818.208 789.432 818.232 ;
    END
  END res_out[55]
  PIN res_out[56]
    DIRECTION OUTPUT ;
    USE SIGNAL ;
    SHAPE ABUTMENT ;
    PORT
      LAYER M4 ;
      RECT 789.240 820.080 789.432 820.104 ;
    END
  END res_out[56]
  PIN res_out[57]
    DIRECTION OUTPUT ;
    USE SIGNAL ;
    SHAPE ABUTMENT ;
    PORT
      LAYER M4 ;
      RECT 789.240 821.952 789.432 821.976 ;
    END
  END res_out[57]
  PIN res_out[58]
    DIRECTION OUTPUT ;
    USE SIGNAL ;
    SHAPE ABUTMENT ;
    PORT
      LAYER M4 ;
      RECT 789.240 823.824 789.432 823.848 ;
    END
  END res_out[58]
  PIN res_out[59]
    DIRECTION OUTPUT ;
    USE SIGNAL ;
    SHAPE ABUTMENT ;
    PORT
      LAYER M4 ;
      RECT 789.240 825.696 789.432 825.720 ;
    END
  END res_out[59]
  PIN res_out[60]
    DIRECTION OUTPUT ;
    USE SIGNAL ;
    SHAPE ABUTMENT ;
    PORT
      LAYER M4 ;
      RECT 789.240 827.616 789.432 827.640 ;
    END
  END res_out[60]
  PIN res_out[61]
    DIRECTION OUTPUT ;
    USE SIGNAL ;
    SHAPE ABUTMENT ;
    PORT
      LAYER M4 ;
      RECT 789.240 829.488 789.432 829.512 ;
    END
  END res_out[61]
  PIN res_out[62]
    DIRECTION OUTPUT ;
    USE SIGNAL ;
    SHAPE ABUTMENT ;
    PORT
      LAYER M4 ;
      RECT 789.240 831.360 789.432 831.384 ;
    END
  END res_out[62]
  PIN res_out[63]
    DIRECTION OUTPUT ;
    USE SIGNAL ;
    SHAPE ABUTMENT ;
    PORT
      LAYER M4 ;
      RECT 789.240 833.232 789.432 833.256 ;
    END
  END res_out[63]
  PIN res_out[64]
    DIRECTION OUTPUT ;
    USE SIGNAL ;
    SHAPE ABUTMENT ;
    PORT
      LAYER M4 ;
      RECT 789.240 835.104 789.432 835.128 ;
    END
  END res_out[64]
  PIN res_out[65]
    DIRECTION OUTPUT ;
    USE SIGNAL ;
    SHAPE ABUTMENT ;
    PORT
      LAYER M4 ;
      RECT 789.240 836.976 789.432 837.000 ;
    END
  END res_out[65]
  PIN res_out[66]
    DIRECTION OUTPUT ;
    USE SIGNAL ;
    SHAPE ABUTMENT ;
    PORT
      LAYER M4 ;
      RECT 789.240 838.896 789.432 838.920 ;
    END
  END res_out[66]
  PIN res_out[67]
    DIRECTION OUTPUT ;
    USE SIGNAL ;
    SHAPE ABUTMENT ;
    PORT
      LAYER M4 ;
      RECT 789.240 840.768 789.432 840.792 ;
    END
  END res_out[67]
  PIN res_out[68]
    DIRECTION OUTPUT ;
    USE SIGNAL ;
    SHAPE ABUTMENT ;
    PORT
      LAYER M4 ;
      RECT 789.240 842.640 789.432 842.664 ;
    END
  END res_out[68]
  PIN res_out[69]
    DIRECTION OUTPUT ;
    USE SIGNAL ;
    SHAPE ABUTMENT ;
    PORT
      LAYER M4 ;
      RECT 789.240 844.512 789.432 844.536 ;
    END
  END res_out[69]
  PIN res_out[70]
    DIRECTION OUTPUT ;
    USE SIGNAL ;
    SHAPE ABUTMENT ;
    PORT
      LAYER M4 ;
      RECT 789.240 846.384 789.432 846.408 ;
    END
  END res_out[70]
  PIN res_out[71]
    DIRECTION OUTPUT ;
    USE SIGNAL ;
    SHAPE ABUTMENT ;
    PORT
      LAYER M4 ;
      RECT 789.240 848.256 789.432 848.280 ;
    END
  END res_out[71]
  PIN res_out[72]
    DIRECTION OUTPUT ;
    USE SIGNAL ;
    SHAPE ABUTMENT ;
    PORT
      LAYER M4 ;
      RECT 789.240 850.176 789.432 850.200 ;
    END
  END res_out[72]
  PIN res_out[73]
    DIRECTION OUTPUT ;
    USE SIGNAL ;
    SHAPE ABUTMENT ;
    PORT
      LAYER M4 ;
      RECT 789.240 852.048 789.432 852.072 ;
    END
  END res_out[73]
  PIN res_out[74]
    DIRECTION OUTPUT ;
    USE SIGNAL ;
    SHAPE ABUTMENT ;
    PORT
      LAYER M4 ;
      RECT 789.240 853.920 789.432 853.944 ;
    END
  END res_out[74]
  PIN res_out[75]
    DIRECTION OUTPUT ;
    USE SIGNAL ;
    SHAPE ABUTMENT ;
    PORT
      LAYER M4 ;
      RECT 789.240 855.792 789.432 855.816 ;
    END
  END res_out[75]
  PIN res_out[76]
    DIRECTION OUTPUT ;
    USE SIGNAL ;
    SHAPE ABUTMENT ;
    PORT
      LAYER M4 ;
      RECT 789.240 857.664 789.432 857.688 ;
    END
  END res_out[76]
  PIN res_out[77]
    DIRECTION OUTPUT ;
    USE SIGNAL ;
    SHAPE ABUTMENT ;
    PORT
      LAYER M4 ;
      RECT 789.240 859.536 789.432 859.560 ;
    END
  END res_out[77]
  PIN res_out[78]
    DIRECTION OUTPUT ;
    USE SIGNAL ;
    SHAPE ABUTMENT ;
    PORT
      LAYER M4 ;
      RECT 789.240 861.408 789.432 861.432 ;
    END
  END res_out[78]
  PIN res_out[79]
    DIRECTION OUTPUT ;
    USE SIGNAL ;
    SHAPE ABUTMENT ;
    PORT
      LAYER M4 ;
      RECT 789.240 863.328 789.432 863.352 ;
    END
  END res_out[79]
  PIN res_out[80]
    DIRECTION OUTPUT ;
    USE SIGNAL ;
    SHAPE ABUTMENT ;
    PORT
      LAYER M4 ;
      RECT 789.240 865.200 789.432 865.224 ;
    END
  END res_out[80]
  PIN res_out[81]
    DIRECTION OUTPUT ;
    USE SIGNAL ;
    SHAPE ABUTMENT ;
    PORT
      LAYER M4 ;
      RECT 789.240 867.072 789.432 867.096 ;
    END
  END res_out[81]
  PIN res_out[82]
    DIRECTION OUTPUT ;
    USE SIGNAL ;
    SHAPE ABUTMENT ;
    PORT
      LAYER M4 ;
      RECT 789.240 868.944 789.432 868.968 ;
    END
  END res_out[82]
  PIN res_out[83]
    DIRECTION OUTPUT ;
    USE SIGNAL ;
    SHAPE ABUTMENT ;
    PORT
      LAYER M4 ;
      RECT 789.240 870.816 789.432 870.840 ;
    END
  END res_out[83]
  PIN res_out[84]
    DIRECTION OUTPUT ;
    USE SIGNAL ;
    SHAPE ABUTMENT ;
    PORT
      LAYER M4 ;
      RECT 789.240 872.688 789.432 872.712 ;
    END
  END res_out[84]
  PIN res_out[85]
    DIRECTION OUTPUT ;
    USE SIGNAL ;
    SHAPE ABUTMENT ;
    PORT
      LAYER M4 ;
      RECT 789.240 874.608 789.432 874.632 ;
    END
  END res_out[85]
  PIN res_out[86]
    DIRECTION OUTPUT ;
    USE SIGNAL ;
    SHAPE ABUTMENT ;
    PORT
      LAYER M4 ;
      RECT 789.240 876.480 789.432 876.504 ;
    END
  END res_out[86]
  PIN res_out[87]
    DIRECTION OUTPUT ;
    USE SIGNAL ;
    SHAPE ABUTMENT ;
    PORT
      LAYER M4 ;
      RECT 789.240 878.352 789.432 878.376 ;
    END
  END res_out[87]
  PIN res_out[88]
    DIRECTION OUTPUT ;
    USE SIGNAL ;
    SHAPE ABUTMENT ;
    PORT
      LAYER M4 ;
      RECT 789.240 880.224 789.432 880.248 ;
    END
  END res_out[88]
  PIN res_out[89]
    DIRECTION OUTPUT ;
    USE SIGNAL ;
    SHAPE ABUTMENT ;
    PORT
      LAYER M4 ;
      RECT 789.240 882.096 789.432 882.120 ;
    END
  END res_out[89]
  PIN res_out[90]
    DIRECTION OUTPUT ;
    USE SIGNAL ;
    SHAPE ABUTMENT ;
    PORT
      LAYER M4 ;
      RECT 789.240 883.968 789.432 883.992 ;
    END
  END res_out[90]
  PIN res_out[91]
    DIRECTION OUTPUT ;
    USE SIGNAL ;
    SHAPE ABUTMENT ;
    PORT
      LAYER M4 ;
      RECT 789.240 885.888 789.432 885.912 ;
    END
  END res_out[91]
  PIN res_out[92]
    DIRECTION OUTPUT ;
    USE SIGNAL ;
    SHAPE ABUTMENT ;
    PORT
      LAYER M4 ;
      RECT 789.240 887.760 789.432 887.784 ;
    END
  END res_out[92]
  PIN res_out[93]
    DIRECTION OUTPUT ;
    USE SIGNAL ;
    SHAPE ABUTMENT ;
    PORT
      LAYER M4 ;
      RECT 789.240 889.632 789.432 889.656 ;
    END
  END res_out[93]
  PIN res_out[94]
    DIRECTION OUTPUT ;
    USE SIGNAL ;
    SHAPE ABUTMENT ;
    PORT
      LAYER M4 ;
      RECT 789.240 891.504 789.432 891.528 ;
    END
  END res_out[94]
  PIN res_out[95]
    DIRECTION OUTPUT ;
    USE SIGNAL ;
    SHAPE ABUTMENT ;
    PORT
      LAYER M4 ;
      RECT 789.240 893.376 789.432 893.400 ;
    END
  END res_out[95]
  PIN res_out[96]
    DIRECTION OUTPUT ;
    USE SIGNAL ;
    SHAPE ABUTMENT ;
    PORT
      LAYER M4 ;
      RECT 789.240 895.248 789.432 895.272 ;
    END
  END res_out[96]
  PIN res_out[97]
    DIRECTION OUTPUT ;
    USE SIGNAL ;
    SHAPE ABUTMENT ;
    PORT
      LAYER M4 ;
      RECT 789.240 897.168 789.432 897.192 ;
    END
  END res_out[97]
  PIN res_out[98]
    DIRECTION OUTPUT ;
    USE SIGNAL ;
    SHAPE ABUTMENT ;
    PORT
      LAYER M4 ;
      RECT 789.240 899.040 789.432 899.064 ;
    END
  END res_out[98]
  PIN res_out[99]
    DIRECTION OUTPUT ;
    USE SIGNAL ;
    SHAPE ABUTMENT ;
    PORT
      LAYER M4 ;
      RECT 789.240 900.912 789.432 900.936 ;
    END
  END res_out[99]
  PIN res_out[100]
    DIRECTION OUTPUT ;
    USE SIGNAL ;
    SHAPE ABUTMENT ;
    PORT
      LAYER M4 ;
      RECT 789.240 902.784 789.432 902.808 ;
    END
  END res_out[100]
  PIN res_out[101]
    DIRECTION OUTPUT ;
    USE SIGNAL ;
    SHAPE ABUTMENT ;
    PORT
      LAYER M4 ;
      RECT 789.240 904.656 789.432 904.680 ;
    END
  END res_out[101]
  PIN res_out[102]
    DIRECTION OUTPUT ;
    USE SIGNAL ;
    SHAPE ABUTMENT ;
    PORT
      LAYER M4 ;
      RECT 789.240 906.528 789.432 906.552 ;
    END
  END res_out[102]
  PIN res_out[103]
    DIRECTION OUTPUT ;
    USE SIGNAL ;
    SHAPE ABUTMENT ;
    PORT
      LAYER M4 ;
      RECT 789.240 908.448 789.432 908.472 ;
    END
  END res_out[103]
  PIN res_out[104]
    DIRECTION OUTPUT ;
    USE SIGNAL ;
    SHAPE ABUTMENT ;
    PORT
      LAYER M4 ;
      RECT 789.240 910.320 789.432 910.344 ;
    END
  END res_out[104]
  PIN res_out[105]
    DIRECTION OUTPUT ;
    USE SIGNAL ;
    SHAPE ABUTMENT ;
    PORT
      LAYER M4 ;
      RECT 789.240 912.192 789.432 912.216 ;
    END
  END res_out[105]
  PIN res_out[106]
    DIRECTION OUTPUT ;
    USE SIGNAL ;
    SHAPE ABUTMENT ;
    PORT
      LAYER M4 ;
      RECT 789.240 914.064 789.432 914.088 ;
    END
  END res_out[106]
  PIN res_out[107]
    DIRECTION OUTPUT ;
    USE SIGNAL ;
    SHAPE ABUTMENT ;
    PORT
      LAYER M4 ;
      RECT 789.240 915.936 789.432 915.960 ;
    END
  END res_out[107]
  PIN res_out[108]
    DIRECTION OUTPUT ;
    USE SIGNAL ;
    SHAPE ABUTMENT ;
    PORT
      LAYER M4 ;
      RECT 789.240 917.808 789.432 917.832 ;
    END
  END res_out[108]
  PIN res_out[109]
    DIRECTION OUTPUT ;
    USE SIGNAL ;
    SHAPE ABUTMENT ;
    PORT
      LAYER M4 ;
      RECT 789.240 919.680 789.432 919.704 ;
    END
  END res_out[109]
  PIN res_out[110]
    DIRECTION OUTPUT ;
    USE SIGNAL ;
    SHAPE ABUTMENT ;
    PORT
      LAYER M4 ;
      RECT 789.240 921.600 789.432 921.624 ;
    END
  END res_out[110]
  PIN res_out[111]
    DIRECTION OUTPUT ;
    USE SIGNAL ;
    SHAPE ABUTMENT ;
    PORT
      LAYER M4 ;
      RECT 789.240 923.472 789.432 923.496 ;
    END
  END res_out[111]
  PIN res_out[112]
    DIRECTION OUTPUT ;
    USE SIGNAL ;
    SHAPE ABUTMENT ;
    PORT
      LAYER M4 ;
      RECT 789.240 925.344 789.432 925.368 ;
    END
  END res_out[112]
  PIN res_out[113]
    DIRECTION OUTPUT ;
    USE SIGNAL ;
    SHAPE ABUTMENT ;
    PORT
      LAYER M4 ;
      RECT 789.240 927.216 789.432 927.240 ;
    END
  END res_out[113]
  PIN res_out[114]
    DIRECTION OUTPUT ;
    USE SIGNAL ;
    SHAPE ABUTMENT ;
    PORT
      LAYER M4 ;
      RECT 789.240 929.088 789.432 929.112 ;
    END
  END res_out[114]
  PIN res_out[115]
    DIRECTION OUTPUT ;
    USE SIGNAL ;
    SHAPE ABUTMENT ;
    PORT
      LAYER M4 ;
      RECT 789.240 930.960 789.432 930.984 ;
    END
  END res_out[115]
  PIN res_out[116]
    DIRECTION OUTPUT ;
    USE SIGNAL ;
    SHAPE ABUTMENT ;
    PORT
      LAYER M4 ;
      RECT 789.240 932.880 789.432 932.904 ;
    END
  END res_out[116]
  PIN res_out[117]
    DIRECTION OUTPUT ;
    USE SIGNAL ;
    SHAPE ABUTMENT ;
    PORT
      LAYER M4 ;
      RECT 789.240 934.752 789.432 934.776 ;
    END
  END res_out[117]
  PIN res_out[118]
    DIRECTION OUTPUT ;
    USE SIGNAL ;
    SHAPE ABUTMENT ;
    PORT
      LAYER M4 ;
      RECT 789.240 936.624 789.432 936.648 ;
    END
  END res_out[118]
  PIN res_out[119]
    DIRECTION OUTPUT ;
    USE SIGNAL ;
    SHAPE ABUTMENT ;
    PORT
      LAYER M4 ;
      RECT 789.240 938.496 789.432 938.520 ;
    END
  END res_out[119]
  PIN res_out[120]
    DIRECTION OUTPUT ;
    USE SIGNAL ;
    SHAPE ABUTMENT ;
    PORT
      LAYER M4 ;
      RECT 789.240 940.368 789.432 940.392 ;
    END
  END res_out[120]
  PIN res_out[121]
    DIRECTION OUTPUT ;
    USE SIGNAL ;
    SHAPE ABUTMENT ;
    PORT
      LAYER M4 ;
      RECT 789.240 942.240 789.432 942.264 ;
    END
  END res_out[121]
  PIN res_out[122]
    DIRECTION OUTPUT ;
    USE SIGNAL ;
    SHAPE ABUTMENT ;
    PORT
      LAYER M4 ;
      RECT 789.240 944.160 789.432 944.184 ;
    END
  END res_out[122]
  PIN res_out[123]
    DIRECTION OUTPUT ;
    USE SIGNAL ;
    SHAPE ABUTMENT ;
    PORT
      LAYER M4 ;
      RECT 789.240 946.032 789.432 946.056 ;
    END
  END res_out[123]
  PIN res_out[124]
    DIRECTION OUTPUT ;
    USE SIGNAL ;
    SHAPE ABUTMENT ;
    PORT
      LAYER M4 ;
      RECT 789.240 947.904 789.432 947.928 ;
    END
  END res_out[124]
  PIN res_out[125]
    DIRECTION OUTPUT ;
    USE SIGNAL ;
    SHAPE ABUTMENT ;
    PORT
      LAYER M4 ;
      RECT 789.240 949.776 789.432 949.800 ;
    END
  END res_out[125]
  PIN res_out[126]
    DIRECTION OUTPUT ;
    USE SIGNAL ;
    SHAPE ABUTMENT ;
    PORT
      LAYER M4 ;
      RECT 789.240 951.648 789.432 951.672 ;
    END
  END res_out[126]
  PIN res_out[127]
    DIRECTION OUTPUT ;
    USE SIGNAL ;
    SHAPE ABUTMENT ;
    PORT
      LAYER M4 ;
      RECT 789.240 953.520 789.432 953.544 ;
    END
  END res_out[127]
  PIN res_out[128]
    DIRECTION OUTPUT ;
    USE SIGNAL ;
    SHAPE ABUTMENT ;
    PORT
      LAYER M4 ;
      RECT 789.240 955.440 789.432 955.464 ;
    END
  END res_out[128]
  PIN res_out[129]
    DIRECTION OUTPUT ;
    USE SIGNAL ;
    SHAPE ABUTMENT ;
    PORT
      LAYER M4 ;
      RECT 789.240 957.312 789.432 957.336 ;
    END
  END res_out[129]
  PIN res_out[130]
    DIRECTION OUTPUT ;
    USE SIGNAL ;
    SHAPE ABUTMENT ;
    PORT
      LAYER M4 ;
      RECT 789.240 959.184 789.432 959.208 ;
    END
  END res_out[130]
  PIN res_out[131]
    DIRECTION OUTPUT ;
    USE SIGNAL ;
    SHAPE ABUTMENT ;
    PORT
      LAYER M4 ;
      RECT 789.240 961.056 789.432 961.080 ;
    END
  END res_out[131]
  PIN res_out[132]
    DIRECTION OUTPUT ;
    USE SIGNAL ;
    SHAPE ABUTMENT ;
    PORT
      LAYER M4 ;
      RECT 789.240 962.928 789.432 962.952 ;
    END
  END res_out[132]
  PIN res_out[133]
    DIRECTION OUTPUT ;
    USE SIGNAL ;
    SHAPE ABUTMENT ;
    PORT
      LAYER M4 ;
      RECT 789.240 964.800 789.432 964.824 ;
    END
  END res_out[133]
  PIN res_out[134]
    DIRECTION OUTPUT ;
    USE SIGNAL ;
    SHAPE ABUTMENT ;
    PORT
      LAYER M4 ;
      RECT 789.240 966.720 789.432 966.744 ;
    END
  END res_out[134]
  PIN res_out[135]
    DIRECTION OUTPUT ;
    USE SIGNAL ;
    SHAPE ABUTMENT ;
    PORT
      LAYER M4 ;
      RECT 789.240 968.592 789.432 968.616 ;
    END
  END res_out[135]
  PIN res_out[136]
    DIRECTION OUTPUT ;
    USE SIGNAL ;
    SHAPE ABUTMENT ;
    PORT
      LAYER M4 ;
      RECT 789.240 970.464 789.432 970.488 ;
    END
  END res_out[136]
  PIN res_out[137]
    DIRECTION OUTPUT ;
    USE SIGNAL ;
    SHAPE ABUTMENT ;
    PORT
      LAYER M4 ;
      RECT 789.240 972.336 789.432 972.360 ;
    END
  END res_out[137]
  PIN res_out[138]
    DIRECTION OUTPUT ;
    USE SIGNAL ;
    SHAPE ABUTMENT ;
    PORT
      LAYER M4 ;
      RECT 789.240 974.208 789.432 974.232 ;
    END
  END res_out[138]
  PIN res_out[139]
    DIRECTION OUTPUT ;
    USE SIGNAL ;
    SHAPE ABUTMENT ;
    PORT
      LAYER M4 ;
      RECT 789.240 976.080 789.432 976.104 ;
    END
  END res_out[139]
  PIN VSS
    DIRECTION INOUT ;
    USE GROUND ;
    PORT
      LAYER M4 ;
      RECT 0.492 1.200 788.940 1.296 ;
      RECT 0.492 3.600 788.940 3.696 ;
      RECT 0.492 6.000 788.940 6.096 ;
      RECT 0.492 8.400 788.940 8.496 ;
      RECT 0.492 10.800 788.940 10.896 ;
      RECT 0.492 13.200 788.940 13.296 ;
      RECT 0.492 15.600 788.940 15.696 ;
      RECT 0.492 18.000 788.940 18.096 ;
      RECT 0.492 20.400 788.940 20.496 ;
      RECT 0.492 22.800 788.940 22.896 ;
      RECT 0.492 25.200 788.940 25.296 ;
      RECT 0.492 27.600 788.940 27.696 ;
      RECT 0.492 30.000 788.940 30.096 ;
      RECT 0.492 32.400 788.940 32.496 ;
      RECT 0.492 34.800 788.940 34.896 ;
      RECT 0.492 37.200 788.940 37.296 ;
      RECT 0.492 39.600 788.940 39.696 ;
      RECT 0.492 42.000 788.940 42.096 ;
      RECT 0.492 44.400 788.940 44.496 ;
      RECT 0.492 46.800 788.940 46.896 ;
      RECT 0.492 49.200 788.940 49.296 ;
      RECT 0.492 51.600 788.940 51.696 ;
      RECT 0.492 54.000 788.940 54.096 ;
      RECT 0.492 56.400 788.940 56.496 ;
      RECT 0.492 58.800 788.940 58.896 ;
      RECT 0.492 61.200 788.940 61.296 ;
      RECT 0.492 63.600 788.940 63.696 ;
      RECT 0.492 66.000 788.940 66.096 ;
      RECT 0.492 68.400 788.940 68.496 ;
      RECT 0.492 70.800 788.940 70.896 ;
      RECT 0.492 73.200 788.940 73.296 ;
      RECT 0.492 75.600 788.940 75.696 ;
      RECT 0.492 78.000 788.940 78.096 ;
      RECT 0.492 80.400 788.940 80.496 ;
      RECT 0.492 82.800 788.940 82.896 ;
      RECT 0.492 85.200 788.940 85.296 ;
      RECT 0.492 87.600 788.940 87.696 ;
      RECT 0.492 90.000 788.940 90.096 ;
      RECT 0.492 92.400 788.940 92.496 ;
      RECT 0.492 94.800 788.940 94.896 ;
      RECT 0.492 97.200 788.940 97.296 ;
      RECT 0.492 99.600 788.940 99.696 ;
      RECT 0.492 102.000 788.940 102.096 ;
      RECT 0.492 104.400 788.940 104.496 ;
      RECT 0.492 106.800 788.940 106.896 ;
      RECT 0.492 109.200 788.940 109.296 ;
      RECT 0.492 111.600 788.940 111.696 ;
      RECT 0.492 114.000 788.940 114.096 ;
      RECT 0.492 116.400 788.940 116.496 ;
      RECT 0.492 118.800 788.940 118.896 ;
      RECT 0.492 121.200 788.940 121.296 ;
      RECT 0.492 123.600 788.940 123.696 ;
      RECT 0.492 126.000 788.940 126.096 ;
      RECT 0.492 128.400 788.940 128.496 ;
      RECT 0.492 130.800 788.940 130.896 ;
      RECT 0.492 133.200 788.940 133.296 ;
      RECT 0.492 135.600 788.940 135.696 ;
      RECT 0.492 138.000 788.940 138.096 ;
      RECT 0.492 140.400 788.940 140.496 ;
      RECT 0.492 142.800 788.940 142.896 ;
      RECT 0.492 145.200 788.940 145.296 ;
      RECT 0.492 147.600 788.940 147.696 ;
      RECT 0.492 150.000 788.940 150.096 ;
      RECT 0.492 152.400 788.940 152.496 ;
      RECT 0.492 154.800 788.940 154.896 ;
      RECT 0.492 157.200 788.940 157.296 ;
      RECT 0.492 159.600 788.940 159.696 ;
      RECT 0.492 162.000 788.940 162.096 ;
      RECT 0.492 164.400 788.940 164.496 ;
      RECT 0.492 166.800 788.940 166.896 ;
      RECT 0.492 169.200 788.940 169.296 ;
      RECT 0.492 171.600 788.940 171.696 ;
      RECT 0.492 174.000 788.940 174.096 ;
      RECT 0.492 176.400 788.940 176.496 ;
      RECT 0.492 178.800 788.940 178.896 ;
      RECT 0.492 181.200 788.940 181.296 ;
      RECT 0.492 183.600 788.940 183.696 ;
      RECT 0.492 186.000 788.940 186.096 ;
      RECT 0.492 188.400 788.940 188.496 ;
      RECT 0.492 190.800 788.940 190.896 ;
      RECT 0.492 193.200 788.940 193.296 ;
      RECT 0.492 195.600 788.940 195.696 ;
      RECT 0.492 198.000 788.940 198.096 ;
      RECT 0.492 200.400 788.940 200.496 ;
      RECT 0.492 202.800 788.940 202.896 ;
      RECT 0.492 205.200 788.940 205.296 ;
      RECT 0.492 207.600 788.940 207.696 ;
      RECT 0.492 210.000 788.940 210.096 ;
      RECT 0.492 212.400 788.940 212.496 ;
      RECT 0.492 214.800 788.940 214.896 ;
      RECT 0.492 217.200 788.940 217.296 ;
      RECT 0.492 219.600 788.940 219.696 ;
      RECT 0.492 222.000 788.940 222.096 ;
      RECT 0.492 224.400 788.940 224.496 ;
      RECT 0.492 226.800 788.940 226.896 ;
      RECT 0.492 229.200 788.940 229.296 ;
      RECT 0.492 231.600 788.940 231.696 ;
      RECT 0.492 234.000 788.940 234.096 ;
      RECT 0.492 236.400 788.940 236.496 ;
      RECT 0.492 238.800 788.940 238.896 ;
      RECT 0.492 241.200 788.940 241.296 ;
      RECT 0.492 243.600 788.940 243.696 ;
      RECT 0.492 246.000 788.940 246.096 ;
      RECT 0.492 248.400 788.940 248.496 ;
      RECT 0.492 250.800 788.940 250.896 ;
      RECT 0.492 253.200 788.940 253.296 ;
      RECT 0.492 255.600 788.940 255.696 ;
      RECT 0.492 258.000 788.940 258.096 ;
      RECT 0.492 260.400 788.940 260.496 ;
      RECT 0.492 262.800 788.940 262.896 ;
      RECT 0.492 265.200 788.940 265.296 ;
      RECT 0.492 267.600 788.940 267.696 ;
      RECT 0.492 270.000 788.940 270.096 ;
      RECT 0.492 272.400 788.940 272.496 ;
      RECT 0.492 274.800 788.940 274.896 ;
      RECT 0.492 277.200 788.940 277.296 ;
      RECT 0.492 279.600 788.940 279.696 ;
      RECT 0.492 282.000 788.940 282.096 ;
      RECT 0.492 284.400 788.940 284.496 ;
      RECT 0.492 286.800 788.940 286.896 ;
      RECT 0.492 289.200 788.940 289.296 ;
      RECT 0.492 291.600 788.940 291.696 ;
      RECT 0.492 294.000 788.940 294.096 ;
      RECT 0.492 296.400 788.940 296.496 ;
      RECT 0.492 298.800 788.940 298.896 ;
      RECT 0.492 301.200 788.940 301.296 ;
      RECT 0.492 303.600 788.940 303.696 ;
      RECT 0.492 306.000 788.940 306.096 ;
      RECT 0.492 308.400 788.940 308.496 ;
      RECT 0.492 310.800 788.940 310.896 ;
      RECT 0.492 313.200 788.940 313.296 ;
      RECT 0.492 315.600 788.940 315.696 ;
      RECT 0.492 318.000 788.940 318.096 ;
      RECT 0.492 320.400 788.940 320.496 ;
      RECT 0.492 322.800 788.940 322.896 ;
      RECT 0.492 325.200 788.940 325.296 ;
      RECT 0.492 327.600 788.940 327.696 ;
      RECT 0.492 330.000 788.940 330.096 ;
      RECT 0.492 332.400 788.940 332.496 ;
      RECT 0.492 334.800 788.940 334.896 ;
      RECT 0.492 337.200 788.940 337.296 ;
      RECT 0.492 339.600 788.940 339.696 ;
      RECT 0.492 342.000 788.940 342.096 ;
      RECT 0.492 344.400 788.940 344.496 ;
      RECT 0.492 346.800 788.940 346.896 ;
      RECT 0.492 349.200 788.940 349.296 ;
      RECT 0.492 351.600 788.940 351.696 ;
      RECT 0.492 354.000 788.940 354.096 ;
      RECT 0.492 356.400 788.940 356.496 ;
      RECT 0.492 358.800 788.940 358.896 ;
      RECT 0.492 361.200 788.940 361.296 ;
      RECT 0.492 363.600 788.940 363.696 ;
      RECT 0.492 366.000 788.940 366.096 ;
      RECT 0.492 368.400 788.940 368.496 ;
      RECT 0.492 370.800 788.940 370.896 ;
      RECT 0.492 373.200 788.940 373.296 ;
      RECT 0.492 375.600 788.940 375.696 ;
      RECT 0.492 378.000 788.940 378.096 ;
      RECT 0.492 380.400 788.940 380.496 ;
      RECT 0.492 382.800 788.940 382.896 ;
      RECT 0.492 385.200 788.940 385.296 ;
      RECT 0.492 387.600 788.940 387.696 ;
      RECT 0.492 390.000 788.940 390.096 ;
      RECT 0.492 392.400 788.940 392.496 ;
      RECT 0.492 394.800 788.940 394.896 ;
      RECT 0.492 397.200 788.940 397.296 ;
      RECT 0.492 399.600 788.940 399.696 ;
      RECT 0.492 402.000 788.940 402.096 ;
      RECT 0.492 404.400 788.940 404.496 ;
      RECT 0.492 406.800 788.940 406.896 ;
      RECT 0.492 409.200 788.940 409.296 ;
      RECT 0.492 411.600 788.940 411.696 ;
      RECT 0.492 414.000 788.940 414.096 ;
      RECT 0.492 416.400 788.940 416.496 ;
      RECT 0.492 418.800 788.940 418.896 ;
      RECT 0.492 421.200 788.940 421.296 ;
      RECT 0.492 423.600 788.940 423.696 ;
      RECT 0.492 426.000 788.940 426.096 ;
      RECT 0.492 428.400 788.940 428.496 ;
      RECT 0.492 430.800 788.940 430.896 ;
      RECT 0.492 433.200 788.940 433.296 ;
      RECT 0.492 435.600 788.940 435.696 ;
      RECT 0.492 438.000 788.940 438.096 ;
      RECT 0.492 440.400 788.940 440.496 ;
      RECT 0.492 442.800 788.940 442.896 ;
      RECT 0.492 445.200 788.940 445.296 ;
      RECT 0.492 447.600 788.940 447.696 ;
      RECT 0.492 450.000 788.940 450.096 ;
      RECT 0.492 452.400 788.940 452.496 ;
      RECT 0.492 454.800 788.940 454.896 ;
      RECT 0.492 457.200 788.940 457.296 ;
      RECT 0.492 459.600 788.940 459.696 ;
      RECT 0.492 462.000 788.940 462.096 ;
      RECT 0.492 464.400 788.940 464.496 ;
      RECT 0.492 466.800 788.940 466.896 ;
      RECT 0.492 469.200 788.940 469.296 ;
      RECT 0.492 471.600 788.940 471.696 ;
      RECT 0.492 474.000 788.940 474.096 ;
      RECT 0.492 476.400 788.940 476.496 ;
      RECT 0.492 478.800 788.940 478.896 ;
      RECT 0.492 481.200 788.940 481.296 ;
      RECT 0.492 483.600 788.940 483.696 ;
      RECT 0.492 486.000 788.940 486.096 ;
      RECT 0.492 488.400 788.940 488.496 ;
      RECT 0.492 490.800 788.940 490.896 ;
      RECT 0.492 493.200 788.940 493.296 ;
      RECT 0.492 495.600 788.940 495.696 ;
      RECT 0.492 498.000 788.940 498.096 ;
      RECT 0.492 500.400 788.940 500.496 ;
      RECT 0.492 502.800 788.940 502.896 ;
      RECT 0.492 505.200 788.940 505.296 ;
      RECT 0.492 507.600 788.940 507.696 ;
      RECT 0.492 510.000 788.940 510.096 ;
      RECT 0.492 512.400 788.940 512.496 ;
      RECT 0.492 514.800 788.940 514.896 ;
      RECT 0.492 517.200 788.940 517.296 ;
      RECT 0.492 519.600 788.940 519.696 ;
      RECT 0.492 522.000 788.940 522.096 ;
      RECT 0.492 524.400 788.940 524.496 ;
      RECT 0.492 526.800 788.940 526.896 ;
      RECT 0.492 529.200 788.940 529.296 ;
      RECT 0.492 531.600 788.940 531.696 ;
      RECT 0.492 534.000 788.940 534.096 ;
      RECT 0.492 536.400 788.940 536.496 ;
      RECT 0.492 538.800 788.940 538.896 ;
      RECT 0.492 541.200 788.940 541.296 ;
      RECT 0.492 543.600 788.940 543.696 ;
      RECT 0.492 546.000 788.940 546.096 ;
      RECT 0.492 548.400 788.940 548.496 ;
      RECT 0.492 550.800 788.940 550.896 ;
      RECT 0.492 553.200 788.940 553.296 ;
      RECT 0.492 555.600 788.940 555.696 ;
      RECT 0.492 558.000 788.940 558.096 ;
      RECT 0.492 560.400 788.940 560.496 ;
      RECT 0.492 562.800 788.940 562.896 ;
      RECT 0.492 565.200 788.940 565.296 ;
      RECT 0.492 567.600 788.940 567.696 ;
      RECT 0.492 570.000 788.940 570.096 ;
      RECT 0.492 572.400 788.940 572.496 ;
      RECT 0.492 574.800 788.940 574.896 ;
      RECT 0.492 577.200 788.940 577.296 ;
      RECT 0.492 579.600 788.940 579.696 ;
      RECT 0.492 582.000 788.940 582.096 ;
      RECT 0.492 584.400 788.940 584.496 ;
      RECT 0.492 586.800 788.940 586.896 ;
      RECT 0.492 589.200 788.940 589.296 ;
      RECT 0.492 591.600 788.940 591.696 ;
      RECT 0.492 594.000 788.940 594.096 ;
      RECT 0.492 596.400 788.940 596.496 ;
      RECT 0.492 598.800 788.940 598.896 ;
      RECT 0.492 601.200 788.940 601.296 ;
      RECT 0.492 603.600 788.940 603.696 ;
      RECT 0.492 606.000 788.940 606.096 ;
      RECT 0.492 608.400 788.940 608.496 ;
      RECT 0.492 610.800 788.940 610.896 ;
      RECT 0.492 613.200 788.940 613.296 ;
      RECT 0.492 615.600 788.940 615.696 ;
      RECT 0.492 618.000 788.940 618.096 ;
      RECT 0.492 620.400 788.940 620.496 ;
      RECT 0.492 622.800 788.940 622.896 ;
      RECT 0.492 625.200 788.940 625.296 ;
      RECT 0.492 627.600 788.940 627.696 ;
      RECT 0.492 630.000 788.940 630.096 ;
      RECT 0.492 632.400 788.940 632.496 ;
      RECT 0.492 634.800 788.940 634.896 ;
      RECT 0.492 637.200 788.940 637.296 ;
      RECT 0.492 639.600 788.940 639.696 ;
      RECT 0.492 642.000 788.940 642.096 ;
      RECT 0.492 644.400 788.940 644.496 ;
      RECT 0.492 646.800 788.940 646.896 ;
      RECT 0.492 649.200 788.940 649.296 ;
      RECT 0.492 651.600 788.940 651.696 ;
      RECT 0.492 654.000 788.940 654.096 ;
      RECT 0.492 656.400 788.940 656.496 ;
      RECT 0.492 658.800 788.940 658.896 ;
      RECT 0.492 661.200 788.940 661.296 ;
      RECT 0.492 663.600 788.940 663.696 ;
      RECT 0.492 666.000 788.940 666.096 ;
      RECT 0.492 668.400 788.940 668.496 ;
      RECT 0.492 670.800 788.940 670.896 ;
      RECT 0.492 673.200 788.940 673.296 ;
      RECT 0.492 675.600 788.940 675.696 ;
      RECT 0.492 678.000 788.940 678.096 ;
      RECT 0.492 680.400 788.940 680.496 ;
      RECT 0.492 682.800 788.940 682.896 ;
      RECT 0.492 685.200 788.940 685.296 ;
      RECT 0.492 687.600 788.940 687.696 ;
      RECT 0.492 690.000 788.940 690.096 ;
      RECT 0.492 692.400 788.940 692.496 ;
      RECT 0.492 694.800 788.940 694.896 ;
      RECT 0.492 697.200 788.940 697.296 ;
      RECT 0.492 699.600 788.940 699.696 ;
      RECT 0.492 702.000 788.940 702.096 ;
      RECT 0.492 704.400 788.940 704.496 ;
      RECT 0.492 706.800 788.940 706.896 ;
      RECT 0.492 709.200 788.940 709.296 ;
      RECT 0.492 711.600 788.940 711.696 ;
      RECT 0.492 714.000 788.940 714.096 ;
      RECT 0.492 716.400 788.940 716.496 ;
      RECT 0.492 718.800 788.940 718.896 ;
      RECT 0.492 721.200 788.940 721.296 ;
      RECT 0.492 723.600 788.940 723.696 ;
      RECT 0.492 726.000 788.940 726.096 ;
      RECT 0.492 728.400 788.940 728.496 ;
      RECT 0.492 730.800 788.940 730.896 ;
      RECT 0.492 733.200 788.940 733.296 ;
      RECT 0.492 735.600 788.940 735.696 ;
      RECT 0.492 738.000 788.940 738.096 ;
      RECT 0.492 740.400 788.940 740.496 ;
      RECT 0.492 742.800 788.940 742.896 ;
      RECT 0.492 745.200 788.940 745.296 ;
      RECT 0.492 747.600 788.940 747.696 ;
      RECT 0.492 750.000 788.940 750.096 ;
      RECT 0.492 752.400 788.940 752.496 ;
      RECT 0.492 754.800 788.940 754.896 ;
      RECT 0.492 757.200 788.940 757.296 ;
      RECT 0.492 759.600 788.940 759.696 ;
      RECT 0.492 762.000 788.940 762.096 ;
      RECT 0.492 764.400 788.940 764.496 ;
      RECT 0.492 766.800 788.940 766.896 ;
      RECT 0.492 769.200 788.940 769.296 ;
      RECT 0.492 771.600 788.940 771.696 ;
      RECT 0.492 774.000 788.940 774.096 ;
      RECT 0.492 776.400 788.940 776.496 ;
      RECT 0.492 778.800 788.940 778.896 ;
      RECT 0.492 781.200 788.940 781.296 ;
      RECT 0.492 783.600 788.940 783.696 ;
      RECT 0.492 786.000 788.940 786.096 ;
      RECT 0.492 788.400 788.940 788.496 ;
      RECT 0.492 790.800 788.940 790.896 ;
      RECT 0.492 793.200 788.940 793.296 ;
      RECT 0.492 795.600 788.940 795.696 ;
      RECT 0.492 798.000 788.940 798.096 ;
      RECT 0.492 800.400 788.940 800.496 ;
      RECT 0.492 802.800 788.940 802.896 ;
      RECT 0.492 805.200 788.940 805.296 ;
      RECT 0.492 807.600 788.940 807.696 ;
      RECT 0.492 810.000 788.940 810.096 ;
      RECT 0.492 812.400 788.940 812.496 ;
      RECT 0.492 814.800 788.940 814.896 ;
      RECT 0.492 817.200 788.940 817.296 ;
      RECT 0.492 819.600 788.940 819.696 ;
      RECT 0.492 822.000 788.940 822.096 ;
      RECT 0.492 824.400 788.940 824.496 ;
      RECT 0.492 826.800 788.940 826.896 ;
      RECT 0.492 829.200 788.940 829.296 ;
      RECT 0.492 831.600 788.940 831.696 ;
      RECT 0.492 834.000 788.940 834.096 ;
      RECT 0.492 836.400 788.940 836.496 ;
      RECT 0.492 838.800 788.940 838.896 ;
      RECT 0.492 841.200 788.940 841.296 ;
      RECT 0.492 843.600 788.940 843.696 ;
      RECT 0.492 846.000 788.940 846.096 ;
      RECT 0.492 848.400 788.940 848.496 ;
      RECT 0.492 850.800 788.940 850.896 ;
      RECT 0.492 853.200 788.940 853.296 ;
      RECT 0.492 855.600 788.940 855.696 ;
      RECT 0.492 858.000 788.940 858.096 ;
      RECT 0.492 860.400 788.940 860.496 ;
      RECT 0.492 862.800 788.940 862.896 ;
      RECT 0.492 865.200 788.940 865.296 ;
      RECT 0.492 867.600 788.940 867.696 ;
      RECT 0.492 870.000 788.940 870.096 ;
      RECT 0.492 872.400 788.940 872.496 ;
      RECT 0.492 874.800 788.940 874.896 ;
      RECT 0.492 877.200 788.940 877.296 ;
      RECT 0.492 879.600 788.940 879.696 ;
      RECT 0.492 882.000 788.940 882.096 ;
      RECT 0.492 884.400 788.940 884.496 ;
      RECT 0.492 886.800 788.940 886.896 ;
      RECT 0.492 889.200 788.940 889.296 ;
      RECT 0.492 891.600 788.940 891.696 ;
      RECT 0.492 894.000 788.940 894.096 ;
      RECT 0.492 896.400 788.940 896.496 ;
      RECT 0.492 898.800 788.940 898.896 ;
      RECT 0.492 901.200 788.940 901.296 ;
      RECT 0.492 903.600 788.940 903.696 ;
      RECT 0.492 906.000 788.940 906.096 ;
      RECT 0.492 908.400 788.940 908.496 ;
      RECT 0.492 910.800 788.940 910.896 ;
      RECT 0.492 913.200 788.940 913.296 ;
      RECT 0.492 915.600 788.940 915.696 ;
      RECT 0.492 918.000 788.940 918.096 ;
      RECT 0.492 920.400 788.940 920.496 ;
      RECT 0.492 922.800 788.940 922.896 ;
      RECT 0.492 925.200 788.940 925.296 ;
      RECT 0.492 927.600 788.940 927.696 ;
      RECT 0.492 930.000 788.940 930.096 ;
      RECT 0.492 932.400 788.940 932.496 ;
      RECT 0.492 934.800 788.940 934.896 ;
      RECT 0.492 937.200 788.940 937.296 ;
      RECT 0.492 939.600 788.940 939.696 ;
      RECT 0.492 942.000 788.940 942.096 ;
      RECT 0.492 944.400 788.940 944.496 ;
      RECT 0.492 946.800 788.940 946.896 ;
      RECT 0.492 949.200 788.940 949.296 ;
      RECT 0.492 951.600 788.940 951.696 ;
      RECT 0.492 954.000 788.940 954.096 ;
      RECT 0.492 956.400 788.940 956.496 ;
      RECT 0.492 958.800 788.940 958.896 ;
      RECT 0.492 961.200 788.940 961.296 ;
      RECT 0.492 963.600 788.940 963.696 ;
      RECT 0.492 966.000 788.940 966.096 ;
      RECT 0.492 968.400 788.940 968.496 ;
      RECT 0.492 970.800 788.940 970.896 ;
      RECT 0.492 973.200 788.940 973.296 ;
      RECT 0.492 975.600 788.940 975.696 ;
    END
  END VSS
  PIN VDD
    DIRECTION INOUT ;
    USE POWER ;
    PORT
      LAYER M4 ;
      RECT 0.492 2.400 788.940 2.496 ;
      RECT 0.492 4.800 788.940 4.896 ;
      RECT 0.492 7.200 788.940 7.296 ;
      RECT 0.492 9.600 788.940 9.696 ;
      RECT 0.492 12.000 788.940 12.096 ;
      RECT 0.492 14.400 788.940 14.496 ;
      RECT 0.492 16.800 788.940 16.896 ;
      RECT 0.492 19.200 788.940 19.296 ;
      RECT 0.492 21.600 788.940 21.696 ;
      RECT 0.492 24.000 788.940 24.096 ;
      RECT 0.492 26.400 788.940 26.496 ;
      RECT 0.492 28.800 788.940 28.896 ;
      RECT 0.492 31.200 788.940 31.296 ;
      RECT 0.492 33.600 788.940 33.696 ;
      RECT 0.492 36.000 788.940 36.096 ;
      RECT 0.492 38.400 788.940 38.496 ;
      RECT 0.492 40.800 788.940 40.896 ;
      RECT 0.492 43.200 788.940 43.296 ;
      RECT 0.492 45.600 788.940 45.696 ;
      RECT 0.492 48.000 788.940 48.096 ;
      RECT 0.492 50.400 788.940 50.496 ;
      RECT 0.492 52.800 788.940 52.896 ;
      RECT 0.492 55.200 788.940 55.296 ;
      RECT 0.492 57.600 788.940 57.696 ;
      RECT 0.492 60.000 788.940 60.096 ;
      RECT 0.492 62.400 788.940 62.496 ;
      RECT 0.492 64.800 788.940 64.896 ;
      RECT 0.492 67.200 788.940 67.296 ;
      RECT 0.492 69.600 788.940 69.696 ;
      RECT 0.492 72.000 788.940 72.096 ;
      RECT 0.492 74.400 788.940 74.496 ;
      RECT 0.492 76.800 788.940 76.896 ;
      RECT 0.492 79.200 788.940 79.296 ;
      RECT 0.492 81.600 788.940 81.696 ;
      RECT 0.492 84.000 788.940 84.096 ;
      RECT 0.492 86.400 788.940 86.496 ;
      RECT 0.492 88.800 788.940 88.896 ;
      RECT 0.492 91.200 788.940 91.296 ;
      RECT 0.492 93.600 788.940 93.696 ;
      RECT 0.492 96.000 788.940 96.096 ;
      RECT 0.492 98.400 788.940 98.496 ;
      RECT 0.492 100.800 788.940 100.896 ;
      RECT 0.492 103.200 788.940 103.296 ;
      RECT 0.492 105.600 788.940 105.696 ;
      RECT 0.492 108.000 788.940 108.096 ;
      RECT 0.492 110.400 788.940 110.496 ;
      RECT 0.492 112.800 788.940 112.896 ;
      RECT 0.492 115.200 788.940 115.296 ;
      RECT 0.492 117.600 788.940 117.696 ;
      RECT 0.492 120.000 788.940 120.096 ;
      RECT 0.492 122.400 788.940 122.496 ;
      RECT 0.492 124.800 788.940 124.896 ;
      RECT 0.492 127.200 788.940 127.296 ;
      RECT 0.492 129.600 788.940 129.696 ;
      RECT 0.492 132.000 788.940 132.096 ;
      RECT 0.492 134.400 788.940 134.496 ;
      RECT 0.492 136.800 788.940 136.896 ;
      RECT 0.492 139.200 788.940 139.296 ;
      RECT 0.492 141.600 788.940 141.696 ;
      RECT 0.492 144.000 788.940 144.096 ;
      RECT 0.492 146.400 788.940 146.496 ;
      RECT 0.492 148.800 788.940 148.896 ;
      RECT 0.492 151.200 788.940 151.296 ;
      RECT 0.492 153.600 788.940 153.696 ;
      RECT 0.492 156.000 788.940 156.096 ;
      RECT 0.492 158.400 788.940 158.496 ;
      RECT 0.492 160.800 788.940 160.896 ;
      RECT 0.492 163.200 788.940 163.296 ;
      RECT 0.492 165.600 788.940 165.696 ;
      RECT 0.492 168.000 788.940 168.096 ;
      RECT 0.492 170.400 788.940 170.496 ;
      RECT 0.492 172.800 788.940 172.896 ;
      RECT 0.492 175.200 788.940 175.296 ;
      RECT 0.492 177.600 788.940 177.696 ;
      RECT 0.492 180.000 788.940 180.096 ;
      RECT 0.492 182.400 788.940 182.496 ;
      RECT 0.492 184.800 788.940 184.896 ;
      RECT 0.492 187.200 788.940 187.296 ;
      RECT 0.492 189.600 788.940 189.696 ;
      RECT 0.492 192.000 788.940 192.096 ;
      RECT 0.492 194.400 788.940 194.496 ;
      RECT 0.492 196.800 788.940 196.896 ;
      RECT 0.492 199.200 788.940 199.296 ;
      RECT 0.492 201.600 788.940 201.696 ;
      RECT 0.492 204.000 788.940 204.096 ;
      RECT 0.492 206.400 788.940 206.496 ;
      RECT 0.492 208.800 788.940 208.896 ;
      RECT 0.492 211.200 788.940 211.296 ;
      RECT 0.492 213.600 788.940 213.696 ;
      RECT 0.492 216.000 788.940 216.096 ;
      RECT 0.492 218.400 788.940 218.496 ;
      RECT 0.492 220.800 788.940 220.896 ;
      RECT 0.492 223.200 788.940 223.296 ;
      RECT 0.492 225.600 788.940 225.696 ;
      RECT 0.492 228.000 788.940 228.096 ;
      RECT 0.492 230.400 788.940 230.496 ;
      RECT 0.492 232.800 788.940 232.896 ;
      RECT 0.492 235.200 788.940 235.296 ;
      RECT 0.492 237.600 788.940 237.696 ;
      RECT 0.492 240.000 788.940 240.096 ;
      RECT 0.492 242.400 788.940 242.496 ;
      RECT 0.492 244.800 788.940 244.896 ;
      RECT 0.492 247.200 788.940 247.296 ;
      RECT 0.492 249.600 788.940 249.696 ;
      RECT 0.492 252.000 788.940 252.096 ;
      RECT 0.492 254.400 788.940 254.496 ;
      RECT 0.492 256.800 788.940 256.896 ;
      RECT 0.492 259.200 788.940 259.296 ;
      RECT 0.492 261.600 788.940 261.696 ;
      RECT 0.492 264.000 788.940 264.096 ;
      RECT 0.492 266.400 788.940 266.496 ;
      RECT 0.492 268.800 788.940 268.896 ;
      RECT 0.492 271.200 788.940 271.296 ;
      RECT 0.492 273.600 788.940 273.696 ;
      RECT 0.492 276.000 788.940 276.096 ;
      RECT 0.492 278.400 788.940 278.496 ;
      RECT 0.492 280.800 788.940 280.896 ;
      RECT 0.492 283.200 788.940 283.296 ;
      RECT 0.492 285.600 788.940 285.696 ;
      RECT 0.492 288.000 788.940 288.096 ;
      RECT 0.492 290.400 788.940 290.496 ;
      RECT 0.492 292.800 788.940 292.896 ;
      RECT 0.492 295.200 788.940 295.296 ;
      RECT 0.492 297.600 788.940 297.696 ;
      RECT 0.492 300.000 788.940 300.096 ;
      RECT 0.492 302.400 788.940 302.496 ;
      RECT 0.492 304.800 788.940 304.896 ;
      RECT 0.492 307.200 788.940 307.296 ;
      RECT 0.492 309.600 788.940 309.696 ;
      RECT 0.492 312.000 788.940 312.096 ;
      RECT 0.492 314.400 788.940 314.496 ;
      RECT 0.492 316.800 788.940 316.896 ;
      RECT 0.492 319.200 788.940 319.296 ;
      RECT 0.492 321.600 788.940 321.696 ;
      RECT 0.492 324.000 788.940 324.096 ;
      RECT 0.492 326.400 788.940 326.496 ;
      RECT 0.492 328.800 788.940 328.896 ;
      RECT 0.492 331.200 788.940 331.296 ;
      RECT 0.492 333.600 788.940 333.696 ;
      RECT 0.492 336.000 788.940 336.096 ;
      RECT 0.492 338.400 788.940 338.496 ;
      RECT 0.492 340.800 788.940 340.896 ;
      RECT 0.492 343.200 788.940 343.296 ;
      RECT 0.492 345.600 788.940 345.696 ;
      RECT 0.492 348.000 788.940 348.096 ;
      RECT 0.492 350.400 788.940 350.496 ;
      RECT 0.492 352.800 788.940 352.896 ;
      RECT 0.492 355.200 788.940 355.296 ;
      RECT 0.492 357.600 788.940 357.696 ;
      RECT 0.492 360.000 788.940 360.096 ;
      RECT 0.492 362.400 788.940 362.496 ;
      RECT 0.492 364.800 788.940 364.896 ;
      RECT 0.492 367.200 788.940 367.296 ;
      RECT 0.492 369.600 788.940 369.696 ;
      RECT 0.492 372.000 788.940 372.096 ;
      RECT 0.492 374.400 788.940 374.496 ;
      RECT 0.492 376.800 788.940 376.896 ;
      RECT 0.492 379.200 788.940 379.296 ;
      RECT 0.492 381.600 788.940 381.696 ;
      RECT 0.492 384.000 788.940 384.096 ;
      RECT 0.492 386.400 788.940 386.496 ;
      RECT 0.492 388.800 788.940 388.896 ;
      RECT 0.492 391.200 788.940 391.296 ;
      RECT 0.492 393.600 788.940 393.696 ;
      RECT 0.492 396.000 788.940 396.096 ;
      RECT 0.492 398.400 788.940 398.496 ;
      RECT 0.492 400.800 788.940 400.896 ;
      RECT 0.492 403.200 788.940 403.296 ;
      RECT 0.492 405.600 788.940 405.696 ;
      RECT 0.492 408.000 788.940 408.096 ;
      RECT 0.492 410.400 788.940 410.496 ;
      RECT 0.492 412.800 788.940 412.896 ;
      RECT 0.492 415.200 788.940 415.296 ;
      RECT 0.492 417.600 788.940 417.696 ;
      RECT 0.492 420.000 788.940 420.096 ;
      RECT 0.492 422.400 788.940 422.496 ;
      RECT 0.492 424.800 788.940 424.896 ;
      RECT 0.492 427.200 788.940 427.296 ;
      RECT 0.492 429.600 788.940 429.696 ;
      RECT 0.492 432.000 788.940 432.096 ;
      RECT 0.492 434.400 788.940 434.496 ;
      RECT 0.492 436.800 788.940 436.896 ;
      RECT 0.492 439.200 788.940 439.296 ;
      RECT 0.492 441.600 788.940 441.696 ;
      RECT 0.492 444.000 788.940 444.096 ;
      RECT 0.492 446.400 788.940 446.496 ;
      RECT 0.492 448.800 788.940 448.896 ;
      RECT 0.492 451.200 788.940 451.296 ;
      RECT 0.492 453.600 788.940 453.696 ;
      RECT 0.492 456.000 788.940 456.096 ;
      RECT 0.492 458.400 788.940 458.496 ;
      RECT 0.492 460.800 788.940 460.896 ;
      RECT 0.492 463.200 788.940 463.296 ;
      RECT 0.492 465.600 788.940 465.696 ;
      RECT 0.492 468.000 788.940 468.096 ;
      RECT 0.492 470.400 788.940 470.496 ;
      RECT 0.492 472.800 788.940 472.896 ;
      RECT 0.492 475.200 788.940 475.296 ;
      RECT 0.492 477.600 788.940 477.696 ;
      RECT 0.492 480.000 788.940 480.096 ;
      RECT 0.492 482.400 788.940 482.496 ;
      RECT 0.492 484.800 788.940 484.896 ;
      RECT 0.492 487.200 788.940 487.296 ;
      RECT 0.492 489.600 788.940 489.696 ;
      RECT 0.492 492.000 788.940 492.096 ;
      RECT 0.492 494.400 788.940 494.496 ;
      RECT 0.492 496.800 788.940 496.896 ;
      RECT 0.492 499.200 788.940 499.296 ;
      RECT 0.492 501.600 788.940 501.696 ;
      RECT 0.492 504.000 788.940 504.096 ;
      RECT 0.492 506.400 788.940 506.496 ;
      RECT 0.492 508.800 788.940 508.896 ;
      RECT 0.492 511.200 788.940 511.296 ;
      RECT 0.492 513.600 788.940 513.696 ;
      RECT 0.492 516.000 788.940 516.096 ;
      RECT 0.492 518.400 788.940 518.496 ;
      RECT 0.492 520.800 788.940 520.896 ;
      RECT 0.492 523.200 788.940 523.296 ;
      RECT 0.492 525.600 788.940 525.696 ;
      RECT 0.492 528.000 788.940 528.096 ;
      RECT 0.492 530.400 788.940 530.496 ;
      RECT 0.492 532.800 788.940 532.896 ;
      RECT 0.492 535.200 788.940 535.296 ;
      RECT 0.492 537.600 788.940 537.696 ;
      RECT 0.492 540.000 788.940 540.096 ;
      RECT 0.492 542.400 788.940 542.496 ;
      RECT 0.492 544.800 788.940 544.896 ;
      RECT 0.492 547.200 788.940 547.296 ;
      RECT 0.492 549.600 788.940 549.696 ;
      RECT 0.492 552.000 788.940 552.096 ;
      RECT 0.492 554.400 788.940 554.496 ;
      RECT 0.492 556.800 788.940 556.896 ;
      RECT 0.492 559.200 788.940 559.296 ;
      RECT 0.492 561.600 788.940 561.696 ;
      RECT 0.492 564.000 788.940 564.096 ;
      RECT 0.492 566.400 788.940 566.496 ;
      RECT 0.492 568.800 788.940 568.896 ;
      RECT 0.492 571.200 788.940 571.296 ;
      RECT 0.492 573.600 788.940 573.696 ;
      RECT 0.492 576.000 788.940 576.096 ;
      RECT 0.492 578.400 788.940 578.496 ;
      RECT 0.492 580.800 788.940 580.896 ;
      RECT 0.492 583.200 788.940 583.296 ;
      RECT 0.492 585.600 788.940 585.696 ;
      RECT 0.492 588.000 788.940 588.096 ;
      RECT 0.492 590.400 788.940 590.496 ;
      RECT 0.492 592.800 788.940 592.896 ;
      RECT 0.492 595.200 788.940 595.296 ;
      RECT 0.492 597.600 788.940 597.696 ;
      RECT 0.492 600.000 788.940 600.096 ;
      RECT 0.492 602.400 788.940 602.496 ;
      RECT 0.492 604.800 788.940 604.896 ;
      RECT 0.492 607.200 788.940 607.296 ;
      RECT 0.492 609.600 788.940 609.696 ;
      RECT 0.492 612.000 788.940 612.096 ;
      RECT 0.492 614.400 788.940 614.496 ;
      RECT 0.492 616.800 788.940 616.896 ;
      RECT 0.492 619.200 788.940 619.296 ;
      RECT 0.492 621.600 788.940 621.696 ;
      RECT 0.492 624.000 788.940 624.096 ;
      RECT 0.492 626.400 788.940 626.496 ;
      RECT 0.492 628.800 788.940 628.896 ;
      RECT 0.492 631.200 788.940 631.296 ;
      RECT 0.492 633.600 788.940 633.696 ;
      RECT 0.492 636.000 788.940 636.096 ;
      RECT 0.492 638.400 788.940 638.496 ;
      RECT 0.492 640.800 788.940 640.896 ;
      RECT 0.492 643.200 788.940 643.296 ;
      RECT 0.492 645.600 788.940 645.696 ;
      RECT 0.492 648.000 788.940 648.096 ;
      RECT 0.492 650.400 788.940 650.496 ;
      RECT 0.492 652.800 788.940 652.896 ;
      RECT 0.492 655.200 788.940 655.296 ;
      RECT 0.492 657.600 788.940 657.696 ;
      RECT 0.492 660.000 788.940 660.096 ;
      RECT 0.492 662.400 788.940 662.496 ;
      RECT 0.492 664.800 788.940 664.896 ;
      RECT 0.492 667.200 788.940 667.296 ;
      RECT 0.492 669.600 788.940 669.696 ;
      RECT 0.492 672.000 788.940 672.096 ;
      RECT 0.492 674.400 788.940 674.496 ;
      RECT 0.492 676.800 788.940 676.896 ;
      RECT 0.492 679.200 788.940 679.296 ;
      RECT 0.492 681.600 788.940 681.696 ;
      RECT 0.492 684.000 788.940 684.096 ;
      RECT 0.492 686.400 788.940 686.496 ;
      RECT 0.492 688.800 788.940 688.896 ;
      RECT 0.492 691.200 788.940 691.296 ;
      RECT 0.492 693.600 788.940 693.696 ;
      RECT 0.492 696.000 788.940 696.096 ;
      RECT 0.492 698.400 788.940 698.496 ;
      RECT 0.492 700.800 788.940 700.896 ;
      RECT 0.492 703.200 788.940 703.296 ;
      RECT 0.492 705.600 788.940 705.696 ;
      RECT 0.492 708.000 788.940 708.096 ;
      RECT 0.492 710.400 788.940 710.496 ;
      RECT 0.492 712.800 788.940 712.896 ;
      RECT 0.492 715.200 788.940 715.296 ;
      RECT 0.492 717.600 788.940 717.696 ;
      RECT 0.492 720.000 788.940 720.096 ;
      RECT 0.492 722.400 788.940 722.496 ;
      RECT 0.492 724.800 788.940 724.896 ;
      RECT 0.492 727.200 788.940 727.296 ;
      RECT 0.492 729.600 788.940 729.696 ;
      RECT 0.492 732.000 788.940 732.096 ;
      RECT 0.492 734.400 788.940 734.496 ;
      RECT 0.492 736.800 788.940 736.896 ;
      RECT 0.492 739.200 788.940 739.296 ;
      RECT 0.492 741.600 788.940 741.696 ;
      RECT 0.492 744.000 788.940 744.096 ;
      RECT 0.492 746.400 788.940 746.496 ;
      RECT 0.492 748.800 788.940 748.896 ;
      RECT 0.492 751.200 788.940 751.296 ;
      RECT 0.492 753.600 788.940 753.696 ;
      RECT 0.492 756.000 788.940 756.096 ;
      RECT 0.492 758.400 788.940 758.496 ;
      RECT 0.492 760.800 788.940 760.896 ;
      RECT 0.492 763.200 788.940 763.296 ;
      RECT 0.492 765.600 788.940 765.696 ;
      RECT 0.492 768.000 788.940 768.096 ;
      RECT 0.492 770.400 788.940 770.496 ;
      RECT 0.492 772.800 788.940 772.896 ;
      RECT 0.492 775.200 788.940 775.296 ;
      RECT 0.492 777.600 788.940 777.696 ;
      RECT 0.492 780.000 788.940 780.096 ;
      RECT 0.492 782.400 788.940 782.496 ;
      RECT 0.492 784.800 788.940 784.896 ;
      RECT 0.492 787.200 788.940 787.296 ;
      RECT 0.492 789.600 788.940 789.696 ;
      RECT 0.492 792.000 788.940 792.096 ;
      RECT 0.492 794.400 788.940 794.496 ;
      RECT 0.492 796.800 788.940 796.896 ;
      RECT 0.492 799.200 788.940 799.296 ;
      RECT 0.492 801.600 788.940 801.696 ;
      RECT 0.492 804.000 788.940 804.096 ;
      RECT 0.492 806.400 788.940 806.496 ;
      RECT 0.492 808.800 788.940 808.896 ;
      RECT 0.492 811.200 788.940 811.296 ;
      RECT 0.492 813.600 788.940 813.696 ;
      RECT 0.492 816.000 788.940 816.096 ;
      RECT 0.492 818.400 788.940 818.496 ;
      RECT 0.492 820.800 788.940 820.896 ;
      RECT 0.492 823.200 788.940 823.296 ;
      RECT 0.492 825.600 788.940 825.696 ;
      RECT 0.492 828.000 788.940 828.096 ;
      RECT 0.492 830.400 788.940 830.496 ;
      RECT 0.492 832.800 788.940 832.896 ;
      RECT 0.492 835.200 788.940 835.296 ;
      RECT 0.492 837.600 788.940 837.696 ;
      RECT 0.492 840.000 788.940 840.096 ;
      RECT 0.492 842.400 788.940 842.496 ;
      RECT 0.492 844.800 788.940 844.896 ;
      RECT 0.492 847.200 788.940 847.296 ;
      RECT 0.492 849.600 788.940 849.696 ;
      RECT 0.492 852.000 788.940 852.096 ;
      RECT 0.492 854.400 788.940 854.496 ;
      RECT 0.492 856.800 788.940 856.896 ;
      RECT 0.492 859.200 788.940 859.296 ;
      RECT 0.492 861.600 788.940 861.696 ;
      RECT 0.492 864.000 788.940 864.096 ;
      RECT 0.492 866.400 788.940 866.496 ;
      RECT 0.492 868.800 788.940 868.896 ;
      RECT 0.492 871.200 788.940 871.296 ;
      RECT 0.492 873.600 788.940 873.696 ;
      RECT 0.492 876.000 788.940 876.096 ;
      RECT 0.492 878.400 788.940 878.496 ;
      RECT 0.492 880.800 788.940 880.896 ;
      RECT 0.492 883.200 788.940 883.296 ;
      RECT 0.492 885.600 788.940 885.696 ;
      RECT 0.492 888.000 788.940 888.096 ;
      RECT 0.492 890.400 788.940 890.496 ;
      RECT 0.492 892.800 788.940 892.896 ;
      RECT 0.492 895.200 788.940 895.296 ;
      RECT 0.492 897.600 788.940 897.696 ;
      RECT 0.492 900.000 788.940 900.096 ;
      RECT 0.492 902.400 788.940 902.496 ;
      RECT 0.492 904.800 788.940 904.896 ;
      RECT 0.492 907.200 788.940 907.296 ;
      RECT 0.492 909.600 788.940 909.696 ;
      RECT 0.492 912.000 788.940 912.096 ;
      RECT 0.492 914.400 788.940 914.496 ;
      RECT 0.492 916.800 788.940 916.896 ;
      RECT 0.492 919.200 788.940 919.296 ;
      RECT 0.492 921.600 788.940 921.696 ;
      RECT 0.492 924.000 788.940 924.096 ;
      RECT 0.492 926.400 788.940 926.496 ;
      RECT 0.492 928.800 788.940 928.896 ;
      RECT 0.492 931.200 788.940 931.296 ;
      RECT 0.492 933.600 788.940 933.696 ;
      RECT 0.492 936.000 788.940 936.096 ;
      RECT 0.492 938.400 788.940 938.496 ;
      RECT 0.492 940.800 788.940 940.896 ;
      RECT 0.492 943.200 788.940 943.296 ;
      RECT 0.492 945.600 788.940 945.696 ;
      RECT 0.492 948.000 788.940 948.096 ;
      RECT 0.492 950.400 788.940 950.496 ;
      RECT 0.492 952.800 788.940 952.896 ;
      RECT 0.492 955.200 788.940 955.296 ;
      RECT 0.492 957.600 788.940 957.696 ;
      RECT 0.492 960.000 788.940 960.096 ;
      RECT 0.492 962.400 788.940 962.496 ;
      RECT 0.492 964.800 788.940 964.896 ;
      RECT 0.492 967.200 788.940 967.296 ;
      RECT 0.492 969.600 788.940 969.696 ;
      RECT 0.492 972.000 788.940 972.096 ;
      RECT 0.492 974.400 788.940 974.496 ;
      RECT 0.492 976.800 788.940 976.896 ;
    END
  END VDD
  OBS
    LAYER M1 ;
    RECT 0 0 789.432 978.504 ;
    LAYER M2 ;
    RECT 0 0 789.432 978.504 ;
    LAYER M3 ;
    RECT 0 0 789.432 978.504 ;
    LAYER M4 ;
    RECT 0 0 789.432 978.504 ;
    LAYER M5 ;
    RECT 0 0 789.432 978.504 ;
    LAYER M6 ;
    RECT 0 0 789.432 978.504 ;
    LAYER M7 ;
    RECT 0 0 789.432 978.504 ;
  END
END ot_pdie_tile_io

END LIBRARY
